VERSION 5.7 ;
  NOWIREEXTENSIONATPIN ON ;
  DIVIDERCHAR "/" ;
  BUSBITCHARS "[]" ;
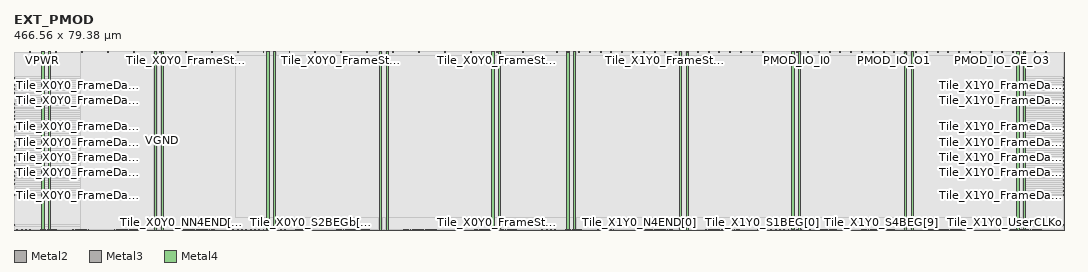
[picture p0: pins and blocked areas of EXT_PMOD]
MACRO EXT_PMOD
  CLASS BLOCK ;
  FOREIGN EXT_PMOD ;
  ORIGIN 0.000 0.000 ;
  SIZE 466.560 BY 79.380 ;
  PIN PMOD_IO_I0
    DIRECTION INPUT ;
    USE SIGNAL ;
    ANTENNAGATEAREA 0.226200 ;
    PORT
      LAYER Metal2 ;
        RECT 347.800 78.980 348.200 79.380 ;
    END
  END PMOD_IO_I0
  PIN PMOD_IO_I1
    DIRECTION INPUT ;
    USE SIGNAL ;
    ANTENNAGATEAREA 0.226200 ;
    PORT
      LAYER Metal2 ;
        RECT 352.600 78.980 353.000 79.380 ;
    END
  END PMOD_IO_I1
  PIN PMOD_IO_I2
    DIRECTION INPUT ;
    USE SIGNAL ;
    ANTENNAGATEAREA 0.226200 ;
    PORT
      LAYER Metal2 ;
        RECT 357.400 78.980 357.800 79.380 ;
    END
  END PMOD_IO_I2
  PIN PMOD_IO_I3
    DIRECTION INPUT ;
    USE SIGNAL ;
    ANTENNAGATEAREA 0.226200 ;
    PORT
      LAYER Metal2 ;
        RECT 362.200 78.980 362.600 79.380 ;
    END
  END PMOD_IO_I3
  PIN PMOD_IO_I4
    DIRECTION INPUT ;
    USE SIGNAL ;
    ANTENNAGATEAREA 0.226200 ;
    PORT
      LAYER Metal2 ;
        RECT 367.000 78.980 367.400 79.380 ;
    END
  END PMOD_IO_I4
  PIN PMOD_IO_I5
    DIRECTION INPUT ;
    USE SIGNAL ;
    ANTENNAGATEAREA 0.226200 ;
    PORT
      LAYER Metal2 ;
        RECT 371.800 78.980 372.200 79.380 ;
    END
  END PMOD_IO_I5
  PIN PMOD_IO_I6
    DIRECTION INPUT ;
    USE SIGNAL ;
    ANTENNAGATEAREA 0.226200 ;
    PORT
      LAYER Metal2 ;
        RECT 376.600 78.980 377.000 79.380 ;
    END
  END PMOD_IO_I6
  PIN PMOD_IO_I7
    DIRECTION INPUT ;
    USE SIGNAL ;
    ANTENNAGATEAREA 0.226200 ;
    PORT
      LAYER Metal2 ;
        RECT 381.400 78.980 381.800 79.380 ;
    END
  END PMOD_IO_I7
  PIN PMOD_IO_O0
    DIRECTION OUTPUT ;
    USE SIGNAL ;
    ANTENNADIFFAREA 2.677400 ;
    PORT
      LAYER Metal2 ;
        RECT 386.200 78.980 386.600 79.380 ;
    END
  END PMOD_IO_O0
  PIN PMOD_IO_O1
    DIRECTION OUTPUT ;
    USE SIGNAL ;
    ANTENNADIFFAREA 2.677400 ;
    PORT
      LAYER Metal2 ;
        RECT 391.000 78.980 391.400 79.380 ;
    END
  END PMOD_IO_O1
  PIN PMOD_IO_O2
    DIRECTION OUTPUT ;
    USE SIGNAL ;
    ANTENNADIFFAREA 2.677400 ;
    PORT
      LAYER Metal2 ;
        RECT 395.800 78.980 396.200 79.380 ;
    END
  END PMOD_IO_O2
  PIN PMOD_IO_O3
    DIRECTION OUTPUT ;
    USE SIGNAL ;
    ANTENNADIFFAREA 2.677400 ;
    PORT
      LAYER Metal2 ;
        RECT 400.600 78.980 401.000 79.380 ;
    END
  END PMOD_IO_O3
  PIN PMOD_IO_O4
    DIRECTION OUTPUT ;
    USE SIGNAL ;
    ANTENNADIFFAREA 2.677400 ;
    PORT
      LAYER Metal2 ;
        RECT 405.400 78.980 405.800 79.380 ;
    END
  END PMOD_IO_O4
  PIN PMOD_IO_O5
    DIRECTION OUTPUT ;
    USE SIGNAL ;
    ANTENNADIFFAREA 2.677400 ;
    PORT
      LAYER Metal2 ;
        RECT 410.200 78.980 410.600 79.380 ;
    END
  END PMOD_IO_O5
  PIN PMOD_IO_O6
    DIRECTION OUTPUT ;
    USE SIGNAL ;
    ANTENNADIFFAREA 2.677400 ;
    PORT
      LAYER Metal2 ;
        RECT 415.000 78.980 415.400 79.380 ;
    END
  END PMOD_IO_O6
  PIN PMOD_IO_O7
    DIRECTION OUTPUT ;
    USE SIGNAL ;
    ANTENNADIFFAREA 2.677400 ;
    PORT
      LAYER Metal2 ;
        RECT 419.800 78.980 420.200 79.380 ;
    END
  END PMOD_IO_O7
  PIN PMOD_IO_OE_O0
    DIRECTION OUTPUT ;
    USE SIGNAL ;
    ANTENNADIFFAREA 2.677400 ;
    PORT
      LAYER Metal2 ;
        RECT 424.600 78.980 425.000 79.380 ;
    END
  END PMOD_IO_OE_O0
  PIN PMOD_IO_OE_O1
    DIRECTION OUTPUT ;
    USE SIGNAL ;
    ANTENNADIFFAREA 3.151000 ;
    PORT
      LAYER Metal2 ;
        RECT 429.400 78.980 429.800 79.380 ;
    END
  END PMOD_IO_OE_O1
  PIN PMOD_IO_OE_O2
    DIRECTION OUTPUT ;
    USE SIGNAL ;
    ANTENNADIFFAREA 3.151000 ;
    PORT
      LAYER Metal2 ;
        RECT 434.200 78.980 434.600 79.380 ;
    END
  END PMOD_IO_OE_O2
  PIN PMOD_IO_OE_O3
    DIRECTION OUTPUT ;
    USE SIGNAL ;
    ANTENNADIFFAREA 3.151000 ;
    PORT
      LAYER Metal2 ;
        RECT 439.000 78.980 439.400 79.380 ;
    END
  END PMOD_IO_OE_O3
  PIN PMOD_IO_OE_O4
    DIRECTION OUTPUT ;
    USE SIGNAL ;
    ANTENNADIFFAREA 2.677400 ;
    PORT
      LAYER Metal2 ;
        RECT 443.800 78.980 444.200 79.380 ;
    END
  END PMOD_IO_OE_O4
  PIN PMOD_IO_OE_O5
    DIRECTION OUTPUT ;
    USE SIGNAL ;
    ANTENNADIFFAREA 2.677400 ;
    PORT
      LAYER Metal2 ;
        RECT 448.600 78.980 449.000 79.380 ;
    END
  END PMOD_IO_OE_O5
  PIN PMOD_IO_OE_O6
    DIRECTION OUTPUT ;
    USE SIGNAL ;
    ANTENNADIFFAREA 2.677400 ;
    PORT
      LAYER Metal2 ;
        RECT 453.400 78.980 453.800 79.380 ;
    END
  END PMOD_IO_OE_O6
  PIN PMOD_IO_OE_O7
    DIRECTION OUTPUT ;
    USE SIGNAL ;
    ANTENNADIFFAREA 3.151000 ;
    PORT
      LAYER Metal2 ;
        RECT 458.200 78.980 458.600 79.380 ;
    END
  END PMOD_IO_OE_O7
  PIN Tile_X0Y0_Ci
    DIRECTION INPUT ;
    USE SIGNAL ;
    PORT
      LAYER Metal2 ;
        RECT 97.240 0.000 97.640 0.400 ;
    END
  END Tile_X0Y0_Ci
  PIN Tile_X0Y0_FrameData[0]
    DIRECTION INPUT ;
    USE SIGNAL ;
    ANTENNAGATEAREA 1.084200 ;
    ANTENNADIFFAREA 36.277199 ;
    PORT
      LAYER Metal3 ;
        RECT 0.000 15.340 0.400 15.740 ;
    END
  END Tile_X0Y0_FrameData[0]
  PIN Tile_X0Y0_FrameData[10]
    DIRECTION INPUT ;
    USE SIGNAL ;
    ANTENNAGATEAREA 1.264900 ;
    ANTENNADIFFAREA 28.215599 ;
    PORT
      LAYER Metal3 ;
        RECT 0.000 32.140 0.400 32.540 ;
    END
  END Tile_X0Y0_FrameData[10]
  PIN Tile_X0Y0_FrameData[11]
    DIRECTION INPUT ;
    USE SIGNAL ;
    ANTENNAGATEAREA 1.264900 ;
    ANTENNADIFFAREA 28.215599 ;
    PORT
      LAYER Metal3 ;
        RECT 0.000 33.820 0.400 34.220 ;
    END
  END Tile_X0Y0_FrameData[11]
  PIN Tile_X0Y0_FrameData[12]
    DIRECTION INPUT ;
    USE SIGNAL ;
    ANTENNAGATEAREA 1.264900 ;
    ANTENNADIFFAREA 14.107800 ;
    PORT
      LAYER Metal3 ;
        RECT 0.000 35.500 0.400 35.900 ;
    END
  END Tile_X0Y0_FrameData[12]
  PIN Tile_X0Y0_FrameData[13]
    DIRECTION INPUT ;
    USE SIGNAL ;
    ANTENNAGATEAREA 1.264900 ;
    ANTENNADIFFAREA 84.646797 ;
    PORT
      LAYER Metal3 ;
        RECT 0.000 37.180 0.400 37.580 ;
    END
  END Tile_X0Y0_FrameData[13]
  PIN Tile_X0Y0_FrameData[14]
    DIRECTION INPUT ;
    USE SIGNAL ;
    ANTENNAGATEAREA 1.264900 ;
    PORT
      LAYER Metal3 ;
        RECT 0.000 38.860 0.400 39.260 ;
    END
  END Tile_X0Y0_FrameData[14]
  PIN Tile_X0Y0_FrameData[15]
    DIRECTION INPUT ;
    USE SIGNAL ;
    ANTENNAGATEAREA 1.445600 ;
    PORT
      LAYER Metal3 ;
        RECT 0.000 40.540 0.400 40.940 ;
    END
  END Tile_X0Y0_FrameData[15]
  PIN Tile_X0Y0_FrameData[16]
    DIRECTION INPUT ;
    USE SIGNAL ;
    ANTENNAGATEAREA 1.445600 ;
    PORT
      LAYER Metal3 ;
        RECT 0.000 42.220 0.400 42.620 ;
    END
  END Tile_X0Y0_FrameData[16]
  PIN Tile_X0Y0_FrameData[17]
    DIRECTION INPUT ;
    USE SIGNAL ;
    ANTENNAGATEAREA 1.445600 ;
    PORT
      LAYER Metal3 ;
        RECT 0.000 43.900 0.400 44.300 ;
    END
  END Tile_X0Y0_FrameData[17]
  PIN Tile_X0Y0_FrameData[18]
    DIRECTION INPUT ;
    USE SIGNAL ;
    ANTENNAGATEAREA 1.445600 ;
    PORT
      LAYER Metal3 ;
        RECT 0.000 45.580 0.400 45.980 ;
    END
  END Tile_X0Y0_FrameData[18]
  PIN Tile_X0Y0_FrameData[19]
    DIRECTION INPUT ;
    USE SIGNAL ;
    ANTENNAGATEAREA 1.445600 ;
    PORT
      LAYER Metal3 ;
        RECT 0.000 47.260 0.400 47.660 ;
    END
  END Tile_X0Y0_FrameData[19]
  PIN Tile_X0Y0_FrameData[1]
    DIRECTION INPUT ;
    USE SIGNAL ;
    ANTENNAGATEAREA 1.084200 ;
    ANTENNADIFFAREA 72.554398 ;
    PORT
      LAYER Metal3 ;
        RECT 0.000 17.020 0.400 17.420 ;
    END
  END Tile_X0Y0_FrameData[1]
  PIN Tile_X0Y0_FrameData[20]
    DIRECTION INPUT ;
    USE SIGNAL ;
    ANTENNAGATEAREA 1.445600 ;
    ANTENNADIFFAREA 16.123199 ;
    PORT
      LAYER Metal3 ;
        RECT 0.000 48.940 0.400 49.340 ;
    END
  END Tile_X0Y0_FrameData[20]
  PIN Tile_X0Y0_FrameData[21]
    DIRECTION INPUT ;
    USE SIGNAL ;
    ANTENNAGATEAREA 1.445600 ;
    PORT
      LAYER Metal3 ;
        RECT 0.000 50.620 0.400 51.020 ;
    END
  END Tile_X0Y0_FrameData[21]
  PIN Tile_X0Y0_FrameData[22]
    DIRECTION INPUT ;
    USE SIGNAL ;
    ANTENNAGATEAREA 1.445600 ;
    PORT
      LAYER Metal3 ;
        RECT 0.000 52.300 0.400 52.700 ;
    END
  END Tile_X0Y0_FrameData[22]
  PIN Tile_X0Y0_FrameData[23]
    DIRECTION INPUT ;
    USE SIGNAL ;
    ANTENNAGATEAREA 1.445600 ;
    PORT
      LAYER Metal3 ;
        RECT 0.000 53.980 0.400 54.380 ;
    END
  END Tile_X0Y0_FrameData[23]
  PIN Tile_X0Y0_FrameData[24]
    DIRECTION INPUT ;
    USE SIGNAL ;
    ANTENNAGATEAREA 1.445600 ;
    PORT
      LAYER Metal3 ;
        RECT 0.000 55.660 0.400 56.060 ;
    END
  END Tile_X0Y0_FrameData[24]
  PIN Tile_X0Y0_FrameData[25]
    DIRECTION INPUT ;
    USE SIGNAL ;
    ANTENNAGATEAREA 1.445600 ;
    PORT
      LAYER Metal3 ;
        RECT 0.000 57.340 0.400 57.740 ;
    END
  END Tile_X0Y0_FrameData[25]
  PIN Tile_X0Y0_FrameData[26]
    DIRECTION INPUT ;
    USE SIGNAL ;
    ANTENNAGATEAREA 1.445600 ;
    ANTENNADIFFAREA 128.985596 ;
    PORT
      LAYER Metal3 ;
        RECT 0.000 59.020 0.400 59.420 ;
    END
  END Tile_X0Y0_FrameData[26]
  PIN Tile_X0Y0_FrameData[27]
    DIRECTION INPUT ;
    USE SIGNAL ;
    ANTENNAGATEAREA 1.445600 ;
    ANTENNADIFFAREA 80.615997 ;
    PORT
      LAYER Metal3 ;
        RECT 0.000 60.700 0.400 61.100 ;
    END
  END Tile_X0Y0_FrameData[27]
  PIN Tile_X0Y0_FrameData[28]
    DIRECTION INPUT ;
    USE SIGNAL ;
    ANTENNAGATEAREA 1.445600 ;
    ANTENNADIFFAREA 16.123199 ;
    PORT
      LAYER Metal3 ;
        RECT 0.000 62.380 0.400 62.780 ;
    END
  END Tile_X0Y0_FrameData[28]
  PIN Tile_X0Y0_FrameData[29]
    DIRECTION INPUT ;
    USE SIGNAL ;
    ANTENNAGATEAREA 1.445600 ;
    PORT
      LAYER Metal3 ;
        RECT 0.000 64.060 0.400 64.460 ;
    END
  END Tile_X0Y0_FrameData[29]
  PIN Tile_X0Y0_FrameData[2]
    DIRECTION INPUT ;
    USE SIGNAL ;
    ANTENNAGATEAREA 1.084200 ;
    ANTENNADIFFAREA 72.554398 ;
    PORT
      LAYER Metal3 ;
        RECT 0.000 18.700 0.400 19.100 ;
    END
  END Tile_X0Y0_FrameData[2]
  PIN Tile_X0Y0_FrameData[30]
    DIRECTION INPUT ;
    USE SIGNAL ;
    ANTENNAGATEAREA 1.445600 ;
    PORT
      LAYER Metal3 ;
        RECT 0.000 65.740 0.400 66.140 ;
    END
  END Tile_X0Y0_FrameData[30]
  PIN Tile_X0Y0_FrameData[31]
    DIRECTION INPUT ;
    USE SIGNAL ;
    ANTENNAGATEAREA 1.445600 ;
    PORT
      LAYER Metal3 ;
        RECT 0.000 67.420 0.400 67.820 ;
    END
  END Tile_X0Y0_FrameData[31]
  PIN Tile_X0Y0_FrameData[3]
    DIRECTION INPUT ;
    USE SIGNAL ;
    ANTENNAGATEAREA 1.084200 ;
    ANTENNADIFFAREA 72.554398 ;
    PORT
      LAYER Metal3 ;
        RECT 0.000 20.380 0.400 20.780 ;
    END
  END Tile_X0Y0_FrameData[3]
  PIN Tile_X0Y0_FrameData[4]
    DIRECTION INPUT ;
    USE SIGNAL ;
    ANTENNAGATEAREA 1.264900 ;
    PORT
      LAYER Metal3 ;
        RECT 0.000 22.060 0.400 22.460 ;
    END
  END Tile_X0Y0_FrameData[4]
  PIN Tile_X0Y0_FrameData[5]
    DIRECTION INPUT ;
    USE SIGNAL ;
    ANTENNAGATEAREA 1.264900 ;
    ANTENNADIFFAREA 98.754601 ;
    PORT
      LAYER Metal3 ;
        RECT 0.000 23.740 0.400 24.140 ;
    END
  END Tile_X0Y0_FrameData[5]
  PIN Tile_X0Y0_FrameData[6]
    DIRECTION INPUT ;
    USE SIGNAL ;
    ANTENNAGATEAREA 1.264900 ;
    PORT
      LAYER Metal3 ;
        RECT 0.000 25.420 0.400 25.820 ;
    END
  END Tile_X0Y0_FrameData[6]
  PIN Tile_X0Y0_FrameData[7]
    DIRECTION INPUT ;
    USE SIGNAL ;
    ANTENNAGATEAREA 1.264900 ;
    ANTENNADIFFAREA 84.646797 ;
    PORT
      LAYER Metal3 ;
        RECT 0.000 27.100 0.400 27.500 ;
    END
  END Tile_X0Y0_FrameData[7]
  PIN Tile_X0Y0_FrameData[8]
    DIRECTION INPUT ;
    USE SIGNAL ;
    ANTENNAGATEAREA 1.264900 ;
    PORT
      LAYER Metal3 ;
        RECT 0.000 28.780 0.400 29.180 ;
    END
  END Tile_X0Y0_FrameData[8]
  PIN Tile_X0Y0_FrameData[9]
    DIRECTION INPUT ;
    USE SIGNAL ;
    ANTENNAGATEAREA 1.264900 ;
    ANTENNADIFFAREA 56.431198 ;
    PORT
      LAYER Metal3 ;
        RECT 0.000 30.460 0.400 30.860 ;
    END
  END Tile_X0Y0_FrameData[9]
  PIN Tile_X0Y0_FrameStrobe[0]
    DIRECTION INPUT ;
    USE SIGNAL ;
    ANTENNAGATEAREA 11.745500 ;
    PORT
      LAYER Metal2 ;
        RECT 204.760 0.000 205.160 0.400 ;
    END
  END Tile_X0Y0_FrameStrobe[0]
  PIN Tile_X0Y0_FrameStrobe[10]
    DIRECTION INPUT ;
    USE SIGNAL ;
    ANTENNAGATEAREA 0.180700 ;
    PORT
      LAYER Metal2 ;
        RECT 214.360 0.000 214.760 0.400 ;
    END
  END Tile_X0Y0_FrameStrobe[10]
  PIN Tile_X0Y0_FrameStrobe[11]
    DIRECTION INPUT ;
    USE SIGNAL ;
    ANTENNAGATEAREA 0.180700 ;
    PORT
      LAYER Metal2 ;
        RECT 215.320 0.000 215.720 0.400 ;
    END
  END Tile_X0Y0_FrameStrobe[11]
  PIN Tile_X0Y0_FrameStrobe[12]
    DIRECTION INPUT ;
    USE SIGNAL ;
    ANTENNAGATEAREA 0.180700 ;
    PORT
      LAYER Metal2 ;
        RECT 216.280 0.000 216.680 0.400 ;
    END
  END Tile_X0Y0_FrameStrobe[12]
  PIN Tile_X0Y0_FrameStrobe[13]
    DIRECTION INPUT ;
    USE SIGNAL ;
    ANTENNAGATEAREA 0.180700 ;
    PORT
      LAYER Metal2 ;
        RECT 217.240 0.000 217.640 0.400 ;
    END
  END Tile_X0Y0_FrameStrobe[13]
  PIN Tile_X0Y0_FrameStrobe[14]
    DIRECTION INPUT ;
    USE SIGNAL ;
    ANTENNAGATEAREA 0.180700 ;
    PORT
      LAYER Metal2 ;
        RECT 218.200 0.000 218.600 0.400 ;
    END
  END Tile_X0Y0_FrameStrobe[14]
  PIN Tile_X0Y0_FrameStrobe[15]
    DIRECTION INPUT ;
    USE SIGNAL ;
    ANTENNAGATEAREA 0.180700 ;
    PORT
      LAYER Metal2 ;
        RECT 219.160 0.000 219.560 0.400 ;
    END
  END Tile_X0Y0_FrameStrobe[15]
  PIN Tile_X0Y0_FrameStrobe[16]
    DIRECTION INPUT ;
    USE SIGNAL ;
    ANTENNAGATEAREA 0.180700 ;
    PORT
      LAYER Metal2 ;
        RECT 220.120 0.000 220.520 0.400 ;
    END
  END Tile_X0Y0_FrameStrobe[16]
  PIN Tile_X0Y0_FrameStrobe[17]
    DIRECTION INPUT ;
    USE SIGNAL ;
    ANTENNAGATEAREA 0.180700 ;
    PORT
      LAYER Metal2 ;
        RECT 221.080 0.000 221.480 0.400 ;
    END
  END Tile_X0Y0_FrameStrobe[17]
  PIN Tile_X0Y0_FrameStrobe[18]
    DIRECTION INPUT ;
    USE SIGNAL ;
    ANTENNAGATEAREA 0.180700 ;
    PORT
      LAYER Metal2 ;
        RECT 222.040 0.000 222.440 0.400 ;
    END
  END Tile_X0Y0_FrameStrobe[18]
  PIN Tile_X0Y0_FrameStrobe[19]
    DIRECTION INPUT ;
    USE SIGNAL ;
    ANTENNAGATEAREA 0.180700 ;
    PORT
      LAYER Metal2 ;
        RECT 223.000 0.000 223.400 0.400 ;
    END
  END Tile_X0Y0_FrameStrobe[19]
  PIN Tile_X0Y0_FrameStrobe[1]
    DIRECTION INPUT ;
    USE SIGNAL ;
    ANTENNAGATEAREA 11.745500 ;
    PORT
      LAYER Metal2 ;
        RECT 205.720 0.000 206.120 0.400 ;
    END
  END Tile_X0Y0_FrameStrobe[1]
  PIN Tile_X0Y0_FrameStrobe[2]
    DIRECTION INPUT ;
    USE SIGNAL ;
    ANTENNAGATEAREA 10.299900 ;
    PORT
      LAYER Metal2 ;
        RECT 206.680 0.000 207.080 0.400 ;
    END
  END Tile_X0Y0_FrameStrobe[2]
  PIN Tile_X0Y0_FrameStrobe[3]
    DIRECTION INPUT ;
    USE SIGNAL ;
    ANTENNAGATEAREA 0.180700 ;
    PORT
      LAYER Metal2 ;
        RECT 207.640 0.000 208.040 0.400 ;
    END
  END Tile_X0Y0_FrameStrobe[3]
  PIN Tile_X0Y0_FrameStrobe[4]
    DIRECTION INPUT ;
    USE SIGNAL ;
    ANTENNAGATEAREA 0.180700 ;
    PORT
      LAYER Metal2 ;
        RECT 208.600 0.000 209.000 0.400 ;
    END
  END Tile_X0Y0_FrameStrobe[4]
  PIN Tile_X0Y0_FrameStrobe[5]
    DIRECTION INPUT ;
    USE SIGNAL ;
    ANTENNAGATEAREA 0.180700 ;
    PORT
      LAYER Metal2 ;
        RECT 209.560 0.000 209.960 0.400 ;
    END
  END Tile_X0Y0_FrameStrobe[5]
  PIN Tile_X0Y0_FrameStrobe[6]
    DIRECTION INPUT ;
    USE SIGNAL ;
    ANTENNAGATEAREA 0.180700 ;
    PORT
      LAYER Metal2 ;
        RECT 210.520 0.000 210.920 0.400 ;
    END
  END Tile_X0Y0_FrameStrobe[6]
  PIN Tile_X0Y0_FrameStrobe[7]
    DIRECTION INPUT ;
    USE SIGNAL ;
    ANTENNAGATEAREA 0.180700 ;
    PORT
      LAYER Metal2 ;
        RECT 211.480 0.000 211.880 0.400 ;
    END
  END Tile_X0Y0_FrameStrobe[7]
  PIN Tile_X0Y0_FrameStrobe[8]
    DIRECTION INPUT ;
    USE SIGNAL ;
    ANTENNAGATEAREA 0.180700 ;
    PORT
      LAYER Metal2 ;
        RECT 212.440 0.000 212.840 0.400 ;
    END
  END Tile_X0Y0_FrameStrobe[8]
  PIN Tile_X0Y0_FrameStrobe[9]
    DIRECTION INPUT ;
    USE SIGNAL ;
    ANTENNAGATEAREA 0.180700 ;
    PORT
      LAYER Metal2 ;
        RECT 213.400 0.000 213.800 0.400 ;
    END
  END Tile_X0Y0_FrameStrobe[9]
  PIN Tile_X0Y0_FrameStrobe_O[0]
    DIRECTION OUTPUT ;
    USE SIGNAL ;
    ANTENNADIFFAREA 2.724000 ;
    PORT
      LAYER Metal2 ;
        RECT 7.000 78.980 7.400 79.380 ;
    END
  END Tile_X0Y0_FrameStrobe_O[0]
  PIN Tile_X0Y0_FrameStrobe_O[10]
    DIRECTION OUTPUT ;
    USE SIGNAL ;
    ANTENNADIFFAREA 2.724000 ;
    PORT
      LAYER Metal2 ;
        RECT 122.200 78.980 122.600 79.380 ;
    END
  END Tile_X0Y0_FrameStrobe_O[10]
  PIN Tile_X0Y0_FrameStrobe_O[11]
    DIRECTION OUTPUT ;
    USE SIGNAL ;
    ANTENNADIFFAREA 2.724000 ;
    PORT
      LAYER Metal2 ;
        RECT 133.720 78.980 134.120 79.380 ;
    END
  END Tile_X0Y0_FrameStrobe_O[11]
  PIN Tile_X0Y0_FrameStrobe_O[12]
    DIRECTION OUTPUT ;
    USE SIGNAL ;
    ANTENNADIFFAREA 2.724000 ;
    PORT
      LAYER Metal2 ;
        RECT 145.240 78.980 145.640 79.380 ;
    END
  END Tile_X0Y0_FrameStrobe_O[12]
  PIN Tile_X0Y0_FrameStrobe_O[13]
    DIRECTION OUTPUT ;
    USE SIGNAL ;
    ANTENNADIFFAREA 2.724000 ;
    PORT
      LAYER Metal2 ;
        RECT 156.760 78.980 157.160 79.380 ;
    END
  END Tile_X0Y0_FrameStrobe_O[13]
  PIN Tile_X0Y0_FrameStrobe_O[14]
    DIRECTION OUTPUT ;
    USE SIGNAL ;
    ANTENNADIFFAREA 2.724000 ;
    PORT
      LAYER Metal2 ;
        RECT 168.280 78.980 168.680 79.380 ;
    END
  END Tile_X0Y0_FrameStrobe_O[14]
  PIN Tile_X0Y0_FrameStrobe_O[15]
    DIRECTION OUTPUT ;
    USE SIGNAL ;
    ANTENNADIFFAREA 2.724000 ;
    PORT
      LAYER Metal2 ;
        RECT 179.800 78.980 180.200 79.380 ;
    END
  END Tile_X0Y0_FrameStrobe_O[15]
  PIN Tile_X0Y0_FrameStrobe_O[16]
    DIRECTION OUTPUT ;
    USE SIGNAL ;
    ANTENNADIFFAREA 2.724000 ;
    PORT
      LAYER Metal2 ;
        RECT 191.320 78.980 191.720 79.380 ;
    END
  END Tile_X0Y0_FrameStrobe_O[16]
  PIN Tile_X0Y0_FrameStrobe_O[17]
    DIRECTION OUTPUT ;
    USE SIGNAL ;
    ANTENNADIFFAREA 2.724000 ;
    PORT
      LAYER Metal2 ;
        RECT 202.840 78.980 203.240 79.380 ;
    END
  END Tile_X0Y0_FrameStrobe_O[17]
  PIN Tile_X0Y0_FrameStrobe_O[18]
    DIRECTION OUTPUT ;
    USE SIGNAL ;
    ANTENNADIFFAREA 2.724000 ;
    PORT
      LAYER Metal2 ;
        RECT 214.360 78.980 214.760 79.380 ;
    END
  END Tile_X0Y0_FrameStrobe_O[18]
  PIN Tile_X0Y0_FrameStrobe_O[19]
    DIRECTION OUTPUT ;
    USE SIGNAL ;
    ANTENNADIFFAREA 2.724000 ;
    PORT
      LAYER Metal2 ;
        RECT 225.880 78.980 226.280 79.380 ;
    END
  END Tile_X0Y0_FrameStrobe_O[19]
  PIN Tile_X0Y0_FrameStrobe_O[1]
    DIRECTION OUTPUT ;
    USE SIGNAL ;
    ANTENNADIFFAREA 2.724000 ;
    PORT
      LAYER Metal2 ;
        RECT 18.520 78.980 18.920 79.380 ;
    END
  END Tile_X0Y0_FrameStrobe_O[1]
  PIN Tile_X0Y0_FrameStrobe_O[2]
    DIRECTION OUTPUT ;
    USE SIGNAL ;
    ANTENNADIFFAREA 2.724000 ;
    PORT
      LAYER Metal2 ;
        RECT 30.040 78.980 30.440 79.380 ;
    END
  END Tile_X0Y0_FrameStrobe_O[2]
  PIN Tile_X0Y0_FrameStrobe_O[3]
    DIRECTION OUTPUT ;
    USE SIGNAL ;
    ANTENNADIFFAREA 2.724000 ;
    PORT
      LAYER Metal2 ;
        RECT 41.560 78.980 41.960 79.380 ;
    END
  END Tile_X0Y0_FrameStrobe_O[3]
  PIN Tile_X0Y0_FrameStrobe_O[4]
    DIRECTION OUTPUT ;
    USE SIGNAL ;
    ANTENNADIFFAREA 2.724000 ;
    PORT
      LAYER Metal2 ;
        RECT 53.080 78.980 53.480 79.380 ;
    END
  END Tile_X0Y0_FrameStrobe_O[4]
  PIN Tile_X0Y0_FrameStrobe_O[5]
    DIRECTION OUTPUT ;
    USE SIGNAL ;
    ANTENNADIFFAREA 2.724000 ;
    PORT
      LAYER Metal2 ;
        RECT 64.600 78.980 65.000 79.380 ;
    END
  END Tile_X0Y0_FrameStrobe_O[5]
  PIN Tile_X0Y0_FrameStrobe_O[6]
    DIRECTION OUTPUT ;
    USE SIGNAL ;
    ANTENNADIFFAREA 2.724000 ;
    PORT
      LAYER Metal2 ;
        RECT 76.120 78.980 76.520 79.380 ;
    END
  END Tile_X0Y0_FrameStrobe_O[6]
  PIN Tile_X0Y0_FrameStrobe_O[7]
    DIRECTION OUTPUT ;
    USE SIGNAL ;
    ANTENNADIFFAREA 2.724000 ;
    PORT
      LAYER Metal2 ;
        RECT 87.640 78.980 88.040 79.380 ;
    END
  END Tile_X0Y0_FrameStrobe_O[7]
  PIN Tile_X0Y0_FrameStrobe_O[8]
    DIRECTION OUTPUT ;
    USE SIGNAL ;
    ANTENNADIFFAREA 2.724000 ;
    PORT
      LAYER Metal2 ;
        RECT 99.160 78.980 99.560 79.380 ;
    END
  END Tile_X0Y0_FrameStrobe_O[8]
  PIN Tile_X0Y0_FrameStrobe_O[9]
    DIRECTION OUTPUT ;
    USE SIGNAL ;
    ANTENNADIFFAREA 2.724000 ;
    PORT
      LAYER Metal2 ;
        RECT 110.680 78.980 111.080 79.380 ;
    END
  END Tile_X0Y0_FrameStrobe_O[9]
  PIN Tile_X0Y0_N1END[0]
    DIRECTION INPUT ;
    USE SIGNAL ;
    ANTENNAGATEAREA 0.607100 ;
    PORT
      LAYER Metal2 ;
        RECT 1.240 0.000 1.640 0.400 ;
    END
  END Tile_X0Y0_N1END[0]
  PIN Tile_X0Y0_N1END[1]
    DIRECTION INPUT ;
    USE SIGNAL ;
    ANTENNAGATEAREA 0.607100 ;
    PORT
      LAYER Metal2 ;
        RECT 3.160 0.000 3.560 0.400 ;
    END
  END Tile_X0Y0_N1END[1]
  PIN Tile_X0Y0_N1END[2]
    DIRECTION INPUT ;
    USE SIGNAL ;
    ANTENNAGATEAREA 0.607100 ;
    PORT
      LAYER Metal2 ;
        RECT 5.080 0.000 5.480 0.400 ;
    END
  END Tile_X0Y0_N1END[2]
  PIN Tile_X0Y0_N1END[3]
    DIRECTION INPUT ;
    USE SIGNAL ;
    ANTENNAGATEAREA 0.607100 ;
    PORT
      LAYER Metal2 ;
        RECT 7.000 0.000 7.400 0.400 ;
    END
  END Tile_X0Y0_N1END[3]
  PIN Tile_X0Y0_N2END[0]
    DIRECTION INPUT ;
    USE SIGNAL ;
    ANTENNAGATEAREA 0.639600 ;
    PORT
      LAYER Metal2 ;
        RECT 26.200 0.000 26.600 0.400 ;
    END
  END Tile_X0Y0_N2END[0]
  PIN Tile_X0Y0_N2END[1]
    DIRECTION INPUT ;
    USE SIGNAL ;
    ANTENNAGATEAREA 0.639600 ;
    PORT
      LAYER Metal2 ;
        RECT 27.160 0.000 27.560 0.400 ;
    END
  END Tile_X0Y0_N2END[1]
  PIN Tile_X0Y0_N2END[2]
    DIRECTION INPUT ;
    USE SIGNAL ;
    ANTENNAGATEAREA 0.852800 ;
    PORT
      LAYER Metal2 ;
        RECT 28.120 0.000 28.520 0.400 ;
    END
  END Tile_X0Y0_N2END[2]
  PIN Tile_X0Y0_N2END[3]
    DIRECTION INPUT ;
    USE SIGNAL ;
    ANTENNAGATEAREA 0.852800 ;
    PORT
      LAYER Metal2 ;
        RECT 29.080 0.000 29.480 0.400 ;
    END
  END Tile_X0Y0_N2END[3]
  PIN Tile_X0Y0_N2END[4]
    DIRECTION INPUT ;
    USE SIGNAL ;
    ANTENNAGATEAREA 0.852800 ;
    ANTENNADIFFAREA 32.246399 ;
    PORT
      LAYER Metal2 ;
        RECT 30.040 0.000 30.440 0.400 ;
    END
  END Tile_X0Y0_N2END[4]
  PIN Tile_X0Y0_N2END[5]
    DIRECTION INPUT ;
    USE SIGNAL ;
    ANTENNAGATEAREA 0.852800 ;
    PORT
      LAYER Metal2 ;
        RECT 31.000 0.000 31.400 0.400 ;
    END
  END Tile_X0Y0_N2END[5]
  PIN Tile_X0Y0_N2END[6]
    DIRECTION INPUT ;
    USE SIGNAL ;
    ANTENNAGATEAREA 0.852800 ;
    PORT
      LAYER Metal2 ;
        RECT 31.960 0.000 32.360 0.400 ;
    END
  END Tile_X0Y0_N2END[6]
  PIN Tile_X0Y0_N2END[7]
    DIRECTION INPUT ;
    USE SIGNAL ;
    ANTENNAGATEAREA 0.852800 ;
    PORT
      LAYER Metal2 ;
        RECT 32.920 0.000 33.320 0.400 ;
    END
  END Tile_X0Y0_N2END[7]
  PIN Tile_X0Y0_N2MID[0]
    DIRECTION INPUT ;
    USE SIGNAL ;
    ANTENNAGATEAREA 1.033500 ;
    PORT
      LAYER Metal2 ;
        RECT 11.800 0.000 12.200 0.400 ;
    END
  END Tile_X0Y0_N2MID[0]
  PIN Tile_X0Y0_N2MID[1]
    DIRECTION INPUT ;
    USE SIGNAL ;
    ANTENNAGATEAREA 1.033500 ;
    PORT
      LAYER Metal2 ;
        RECT 12.760 0.000 13.160 0.400 ;
    END
  END Tile_X0Y0_N2MID[1]
  PIN Tile_X0Y0_N2MID[2]
    DIRECTION INPUT ;
    USE SIGNAL ;
    ANTENNAGATEAREA 1.033500 ;
    PORT
      LAYER Metal2 ;
        RECT 13.720 0.000 14.120 0.400 ;
    END
  END Tile_X0Y0_N2MID[2]
  PIN Tile_X0Y0_N2MID[3]
    DIRECTION INPUT ;
    USE SIGNAL ;
    ANTENNAGATEAREA 1.033500 ;
    PORT
      LAYER Metal2 ;
        RECT 14.680 0.000 15.080 0.400 ;
    END
  END Tile_X0Y0_N2MID[3]
  PIN Tile_X0Y0_N2MID[4]
    DIRECTION INPUT ;
    USE SIGNAL ;
    ANTENNAGATEAREA 1.033500 ;
    PORT
      LAYER Metal2 ;
        RECT 15.640 0.000 16.040 0.400 ;
    END
  END Tile_X0Y0_N2MID[4]
  PIN Tile_X0Y0_N2MID[5]
    DIRECTION INPUT ;
    USE SIGNAL ;
    ANTENNAGATEAREA 1.033500 ;
    PORT
      LAYER Metal2 ;
        RECT 16.600 0.000 17.000 0.400 ;
    END
  END Tile_X0Y0_N2MID[5]
  PIN Tile_X0Y0_N2MID[6]
    DIRECTION INPUT ;
    USE SIGNAL ;
    ANTENNAGATEAREA 0.820300 ;
    PORT
      LAYER Metal2 ;
        RECT 17.560 0.000 17.960 0.400 ;
    END
  END Tile_X0Y0_N2MID[6]
  PIN Tile_X0Y0_N2MID[7]
    DIRECTION INPUT ;
    USE SIGNAL ;
    ANTENNAGATEAREA 0.820300 ;
    PORT
      LAYER Metal2 ;
        RECT 18.520 0.000 18.920 0.400 ;
    END
  END Tile_X0Y0_N2MID[7]
  PIN Tile_X0Y0_N4END[0]
    DIRECTION INPUT ;
    USE SIGNAL ;
    ANTENNAGATEAREA 0.426400 ;
    PORT
      LAYER Metal2 ;
        RECT 44.440 0.000 44.840 0.400 ;
    END
  END Tile_X0Y0_N4END[0]
  PIN Tile_X0Y0_N4END[10]
    DIRECTION INPUT ;
    USE SIGNAL ;
    ANTENNAGATEAREA 0.639600 ;
    PORT
      LAYER Metal2 ;
        RECT 54.040 0.000 54.440 0.400 ;
    END
  END Tile_X0Y0_N4END[10]
  PIN Tile_X0Y0_N4END[11]
    DIRECTION INPUT ;
    USE SIGNAL ;
    ANTENNAGATEAREA 0.639600 ;
    PORT
      LAYER Metal2 ;
        RECT 55.000 0.000 55.400 0.400 ;
    END
  END Tile_X0Y0_N4END[11]
  PIN Tile_X0Y0_N4END[12]
    DIRECTION INPUT ;
    USE SIGNAL ;
    ANTENNAGATEAREA 0.639600 ;
    PORT
      LAYER Metal2 ;
        RECT 55.960 0.000 56.360 0.400 ;
    END
  END Tile_X0Y0_N4END[12]
  PIN Tile_X0Y0_N4END[13]
    DIRECTION INPUT ;
    USE SIGNAL ;
    ANTENNAGATEAREA 0.639600 ;
    PORT
      LAYER Metal2 ;
        RECT 56.920 0.000 57.320 0.400 ;
    END
  END Tile_X0Y0_N4END[13]
  PIN Tile_X0Y0_N4END[14]
    DIRECTION INPUT ;
    USE SIGNAL ;
    ANTENNAGATEAREA 0.426400 ;
    ANTENNADIFFAREA 8.061600 ;
    PORT
      LAYER Metal2 ;
        RECT 57.880 0.000 58.280 0.400 ;
    END
  END Tile_X0Y0_N4END[14]
  PIN Tile_X0Y0_N4END[15]
    DIRECTION INPUT ;
    USE SIGNAL ;
    ANTENNAGATEAREA 0.426400 ;
    PORT
      LAYER Metal2 ;
        RECT 58.840 0.000 59.240 0.400 ;
    END
  END Tile_X0Y0_N4END[15]
  PIN Tile_X0Y0_N4END[1]
    DIRECTION INPUT ;
    USE SIGNAL ;
    ANTENNAGATEAREA 0.426400 ;
    PORT
      LAYER Metal2 ;
        RECT 45.400 0.000 45.800 0.400 ;
    END
  END Tile_X0Y0_N4END[1]
  PIN Tile_X0Y0_N4END[2]
    DIRECTION INPUT ;
    USE SIGNAL ;
    ANTENNAGATEAREA 0.426400 ;
    PORT
      LAYER Metal2 ;
        RECT 46.360 0.000 46.760 0.400 ;
    END
  END Tile_X0Y0_N4END[2]
  PIN Tile_X0Y0_N4END[3]
    DIRECTION INPUT ;
    USE SIGNAL ;
    ANTENNAGATEAREA 0.426400 ;
    ANTENNADIFFAREA 8.061600 ;
    PORT
      LAYER Metal2 ;
        RECT 47.320 0.000 47.720 0.400 ;
    END
  END Tile_X0Y0_N4END[3]
  PIN Tile_X0Y0_N4END[4]
    DIRECTION INPUT ;
    USE SIGNAL ;
    ANTENNAGATEAREA 0.426400 ;
    PORT
      LAYER Metal2 ;
        RECT 48.280 0.000 48.680 0.400 ;
    END
  END Tile_X0Y0_N4END[4]
  PIN Tile_X0Y0_N4END[5]
    DIRECTION INPUT ;
    USE SIGNAL ;
    ANTENNAGATEAREA 0.426400 ;
    PORT
      LAYER Metal2 ;
        RECT 49.240 0.000 49.640 0.400 ;
    END
  END Tile_X0Y0_N4END[5]
  PIN Tile_X0Y0_N4END[6]
    DIRECTION INPUT ;
    USE SIGNAL ;
    ANTENNAGATEAREA 0.426400 ;
    PORT
      LAYER Metal2 ;
        RECT 50.200 0.000 50.600 0.400 ;
    END
  END Tile_X0Y0_N4END[6]
  PIN Tile_X0Y0_N4END[7]
    DIRECTION INPUT ;
    USE SIGNAL ;
    ANTENNAGATEAREA 0.426400 ;
    PORT
      LAYER Metal2 ;
        RECT 51.160 0.000 51.560 0.400 ;
    END
  END Tile_X0Y0_N4END[7]
  PIN Tile_X0Y0_N4END[8]
    DIRECTION INPUT ;
    USE SIGNAL ;
    ANTENNAGATEAREA 0.639600 ;
    PORT
      LAYER Metal2 ;
        RECT 52.120 0.000 52.520 0.400 ;
    END
  END Tile_X0Y0_N4END[8]
  PIN Tile_X0Y0_N4END[9]
    DIRECTION INPUT ;
    USE SIGNAL ;
    ANTENNAGATEAREA 0.639600 ;
    PORT
      LAYER Metal2 ;
        RECT 53.080 0.000 53.480 0.400 ;
    END
  END Tile_X0Y0_N4END[9]
  PIN Tile_X0Y0_NN4END[0]
    DIRECTION INPUT ;
    USE SIGNAL ;
    ANTENNAGATEAREA 0.426400 ;
    PORT
      LAYER Metal2 ;
        RECT 74.200 0.000 74.600 0.400 ;
    END
  END Tile_X0Y0_NN4END[0]
  PIN Tile_X0Y0_NN4END[10]
    DIRECTION INPUT ;
    USE SIGNAL ;
    ANTENNAGATEAREA 0.639600 ;
    PORT
      LAYER Metal2 ;
        RECT 83.800 0.000 84.200 0.400 ;
    END
  END Tile_X0Y0_NN4END[10]
  PIN Tile_X0Y0_NN4END[11]
    DIRECTION INPUT ;
    USE SIGNAL ;
    ANTENNAGATEAREA 0.639600 ;
    PORT
      LAYER Metal2 ;
        RECT 84.760 0.000 85.160 0.400 ;
    END
  END Tile_X0Y0_NN4END[11]
  PIN Tile_X0Y0_NN4END[12]
    DIRECTION INPUT ;
    USE SIGNAL ;
    ANTENNAGATEAREA 0.639600 ;
    PORT
      LAYER Metal2 ;
        RECT 85.720 0.000 86.120 0.400 ;
    END
  END Tile_X0Y0_NN4END[12]
  PIN Tile_X0Y0_NN4END[13]
    DIRECTION INPUT ;
    USE SIGNAL ;
    ANTENNAGATEAREA 0.639600 ;
    PORT
      LAYER Metal2 ;
        RECT 86.680 0.000 87.080 0.400 ;
    END
  END Tile_X0Y0_NN4END[13]
  PIN Tile_X0Y0_NN4END[14]
    DIRECTION INPUT ;
    USE SIGNAL ;
    ANTENNAGATEAREA 0.426400 ;
    PORT
      LAYER Metal2 ;
        RECT 87.640 0.000 88.040 0.400 ;
    END
  END Tile_X0Y0_NN4END[14]
  PIN Tile_X0Y0_NN4END[15]
    DIRECTION INPUT ;
    USE SIGNAL ;
    ANTENNAGATEAREA 0.426400 ;
    PORT
      LAYER Metal2 ;
        RECT 88.600 0.000 89.000 0.400 ;
    END
  END Tile_X0Y0_NN4END[15]
  PIN Tile_X0Y0_NN4END[1]
    DIRECTION INPUT ;
    USE SIGNAL ;
    ANTENNAGATEAREA 0.426400 ;
    PORT
      LAYER Metal2 ;
        RECT 75.160 0.000 75.560 0.400 ;
    END
  END Tile_X0Y0_NN4END[1]
  PIN Tile_X0Y0_NN4END[2]
    DIRECTION INPUT ;
    USE SIGNAL ;
    ANTENNAGATEAREA 0.426400 ;
    PORT
      LAYER Metal2 ;
        RECT 76.120 0.000 76.520 0.400 ;
    END
  END Tile_X0Y0_NN4END[2]
  PIN Tile_X0Y0_NN4END[3]
    DIRECTION INPUT ;
    USE SIGNAL ;
    ANTENNAGATEAREA 0.426400 ;
    PORT
      LAYER Metal2 ;
        RECT 77.080 0.000 77.480 0.400 ;
    END
  END Tile_X0Y0_NN4END[3]
  PIN Tile_X0Y0_NN4END[4]
    DIRECTION INPUT ;
    USE SIGNAL ;
    ANTENNAGATEAREA 0.426400 ;
    PORT
      LAYER Metal2 ;
        RECT 78.040 0.000 78.440 0.400 ;
    END
  END Tile_X0Y0_NN4END[4]
  PIN Tile_X0Y0_NN4END[5]
    DIRECTION INPUT ;
    USE SIGNAL ;
    ANTENNAGATEAREA 0.426400 ;
    PORT
      LAYER Metal2 ;
        RECT 79.000 0.000 79.400 0.400 ;
    END
  END Tile_X0Y0_NN4END[5]
  PIN Tile_X0Y0_NN4END[6]
    DIRECTION INPUT ;
    USE SIGNAL ;
    ANTENNAGATEAREA 0.426400 ;
    PORT
      LAYER Metal2 ;
        RECT 79.960 0.000 80.360 0.400 ;
    END
  END Tile_X0Y0_NN4END[6]
  PIN Tile_X0Y0_NN4END[7]
    DIRECTION INPUT ;
    USE SIGNAL ;
    ANTENNAGATEAREA 0.426400 ;
    PORT
      LAYER Metal2 ;
        RECT 80.920 0.000 81.320 0.400 ;
    END
  END Tile_X0Y0_NN4END[7]
  PIN Tile_X0Y0_NN4END[8]
    DIRECTION INPUT ;
    USE SIGNAL ;
    ANTENNAGATEAREA 0.639600 ;
    PORT
      LAYER Metal2 ;
        RECT 81.880 0.000 82.280 0.400 ;
    END
  END Tile_X0Y0_NN4END[8]
  PIN Tile_X0Y0_NN4END[9]
    DIRECTION INPUT ;
    USE SIGNAL ;
    ANTENNAGATEAREA 0.639600 ;
    PORT
      LAYER Metal2 ;
        RECT 82.840 0.000 83.240 0.400 ;
    END
  END Tile_X0Y0_NN4END[9]
  PIN Tile_X0Y0_S1BEG[0]
    DIRECTION OUTPUT ;
    USE SIGNAL ;
    ANTENNADIFFAREA 2.724000 ;
    PORT
      LAYER Metal2 ;
        RECT 99.160 0.000 99.560 0.400 ;
    END
  END Tile_X0Y0_S1BEG[0]
  PIN Tile_X0Y0_S1BEG[1]
    DIRECTION OUTPUT ;
    USE SIGNAL ;
    ANTENNADIFFAREA 2.724000 ;
    PORT
      LAYER Metal2 ;
        RECT 101.080 0.000 101.480 0.400 ;
    END
  END Tile_X0Y0_S1BEG[1]
  PIN Tile_X0Y0_S1BEG[2]
    DIRECTION OUTPUT ;
    USE SIGNAL ;
    ANTENNADIFFAREA 2.724000 ;
    PORT
      LAYER Metal2 ;
        RECT 103.000 0.000 103.400 0.400 ;
    END
  END Tile_X0Y0_S1BEG[2]
  PIN Tile_X0Y0_S1BEG[3]
    DIRECTION OUTPUT ;
    USE SIGNAL ;
    ANTENNADIFFAREA 2.724000 ;
    PORT
      LAYER Metal2 ;
        RECT 104.920 0.000 105.320 0.400 ;
    END
  END Tile_X0Y0_S1BEG[3]
  PIN Tile_X0Y0_S2BEG[0]
    DIRECTION OUTPUT ;
    USE SIGNAL ;
    ANTENNADIFFAREA 2.724000 ;
    PORT
      LAYER Metal2 ;
        RECT 106.840 0.000 107.240 0.400 ;
    END
  END Tile_X0Y0_S2BEG[0]
  PIN Tile_X0Y0_S2BEG[1]
    DIRECTION OUTPUT ;
    USE SIGNAL ;
    ANTENNADIFFAREA 2.724000 ;
    PORT
      LAYER Metal2 ;
        RECT 108.760 0.000 109.160 0.400 ;
    END
  END Tile_X0Y0_S2BEG[1]
  PIN Tile_X0Y0_S2BEG[2]
    DIRECTION OUTPUT ;
    USE SIGNAL ;
    ANTENNADIFFAREA 2.724000 ;
    PORT
      LAYER Metal2 ;
        RECT 110.680 0.000 111.080 0.400 ;
    END
  END Tile_X0Y0_S2BEG[2]
  PIN Tile_X0Y0_S2BEG[3]
    DIRECTION OUTPUT ;
    USE SIGNAL ;
    ANTENNADIFFAREA 2.724000 ;
    PORT
      LAYER Metal2 ;
        RECT 112.600 0.000 113.000 0.400 ;
    END
  END Tile_X0Y0_S2BEG[3]
  PIN Tile_X0Y0_S2BEG[4]
    DIRECTION OUTPUT ;
    USE SIGNAL ;
    ANTENNADIFFAREA 2.724000 ;
    PORT
      LAYER Metal2 ;
        RECT 114.520 0.000 114.920 0.400 ;
    END
  END Tile_X0Y0_S2BEG[4]
  PIN Tile_X0Y0_S2BEG[5]
    DIRECTION OUTPUT ;
    USE SIGNAL ;
    ANTENNADIFFAREA 2.724000 ;
    PORT
      LAYER Metal2 ;
        RECT 116.440 0.000 116.840 0.400 ;
    END
  END Tile_X0Y0_S2BEG[5]
  PIN Tile_X0Y0_S2BEG[6]
    DIRECTION OUTPUT ;
    USE SIGNAL ;
    ANTENNADIFFAREA 2.724000 ;
    PORT
      LAYER Metal2 ;
        RECT 118.360 0.000 118.760 0.400 ;
    END
  END Tile_X0Y0_S2BEG[6]
  PIN Tile_X0Y0_S2BEG[7]
    DIRECTION OUTPUT ;
    USE SIGNAL ;
    ANTENNADIFFAREA 2.724000 ;
    PORT
      LAYER Metal2 ;
        RECT 120.280 0.000 120.680 0.400 ;
    END
  END Tile_X0Y0_S2BEG[7]
  PIN Tile_X0Y0_S2BEGb[0]
    DIRECTION OUTPUT ;
    USE SIGNAL ;
    ANTENNADIFFAREA 2.724000 ;
    PORT
      LAYER Metal2 ;
        RECT 125.080 0.000 125.480 0.400 ;
    END
  END Tile_X0Y0_S2BEGb[0]
  PIN Tile_X0Y0_S2BEGb[1]
    DIRECTION OUTPUT ;
    USE SIGNAL ;
    ANTENNADIFFAREA 2.724000 ;
    PORT
      LAYER Metal2 ;
        RECT 126.040 0.000 126.440 0.400 ;
    END
  END Tile_X0Y0_S2BEGb[1]
  PIN Tile_X0Y0_S2BEGb[2]
    DIRECTION OUTPUT ;
    USE SIGNAL ;
    ANTENNADIFFAREA 2.724000 ;
    PORT
      LAYER Metal2 ;
        RECT 127.000 0.000 127.400 0.400 ;
    END
  END Tile_X0Y0_S2BEGb[2]
  PIN Tile_X0Y0_S2BEGb[3]
    DIRECTION OUTPUT ;
    USE SIGNAL ;
    ANTENNADIFFAREA 2.724000 ;
    PORT
      LAYER Metal2 ;
        RECT 127.960 0.000 128.360 0.400 ;
    END
  END Tile_X0Y0_S2BEGb[3]
  PIN Tile_X0Y0_S2BEGb[4]
    DIRECTION OUTPUT ;
    USE SIGNAL ;
    ANTENNADIFFAREA 2.724000 ;
    PORT
      LAYER Metal2 ;
        RECT 128.920 0.000 129.320 0.400 ;
    END
  END Tile_X0Y0_S2BEGb[4]
  PIN Tile_X0Y0_S2BEGb[5]
    DIRECTION OUTPUT ;
    USE SIGNAL ;
    ANTENNADIFFAREA 2.724000 ;
    PORT
      LAYER Metal2 ;
        RECT 129.880 0.000 130.280 0.400 ;
    END
  END Tile_X0Y0_S2BEGb[5]
  PIN Tile_X0Y0_S2BEGb[6]
    DIRECTION OUTPUT ;
    USE SIGNAL ;
    ANTENNADIFFAREA 2.724000 ;
    PORT
      LAYER Metal2 ;
        RECT 130.840 0.000 131.240 0.400 ;
    END
  END Tile_X0Y0_S2BEGb[6]
  PIN Tile_X0Y0_S2BEGb[7]
    DIRECTION OUTPUT ;
    USE SIGNAL ;
    ANTENNADIFFAREA 2.724000 ;
    PORT
      LAYER Metal2 ;
        RECT 131.800 0.000 132.200 0.400 ;
    END
  END Tile_X0Y0_S2BEGb[7]
  PIN Tile_X0Y0_S4BEG[0]
    DIRECTION OUTPUT ;
    USE SIGNAL ;
    ANTENNADIFFAREA 2.724000 ;
    PORT
      LAYER Metal2 ;
        RECT 143.320 0.000 143.720 0.400 ;
    END
  END Tile_X0Y0_S4BEG[0]
  PIN Tile_X0Y0_S4BEG[10]
    DIRECTION OUTPUT ;
    USE SIGNAL ;
    ANTENNADIFFAREA 2.724000 ;
    PORT
      LAYER Metal2 ;
        RECT 152.920 0.000 153.320 0.400 ;
    END
  END Tile_X0Y0_S4BEG[10]
  PIN Tile_X0Y0_S4BEG[11]
    DIRECTION OUTPUT ;
    USE SIGNAL ;
    ANTENNADIFFAREA 2.724000 ;
    PORT
      LAYER Metal2 ;
        RECT 153.880 0.000 154.280 0.400 ;
    END
  END Tile_X0Y0_S4BEG[11]
  PIN Tile_X0Y0_S4BEG[12]
    DIRECTION OUTPUT ;
    USE SIGNAL ;
    ANTENNADIFFAREA 2.724000 ;
    PORT
      LAYER Metal2 ;
        RECT 154.840 0.000 155.240 0.400 ;
    END
  END Tile_X0Y0_S4BEG[12]
  PIN Tile_X0Y0_S4BEG[13]
    DIRECTION OUTPUT ;
    USE SIGNAL ;
    ANTENNADIFFAREA 2.724000 ;
    PORT
      LAYER Metal2 ;
        RECT 155.800 0.000 156.200 0.400 ;
    END
  END Tile_X0Y0_S4BEG[13]
  PIN Tile_X0Y0_S4BEG[14]
    DIRECTION OUTPUT ;
    USE SIGNAL ;
    ANTENNADIFFAREA 2.724000 ;
    PORT
      LAYER Metal2 ;
        RECT 156.760 0.000 157.160 0.400 ;
    END
  END Tile_X0Y0_S4BEG[14]
  PIN Tile_X0Y0_S4BEG[15]
    DIRECTION OUTPUT ;
    USE SIGNAL ;
    ANTENNADIFFAREA 2.724000 ;
    PORT
      LAYER Metal2 ;
        RECT 157.720 0.000 158.120 0.400 ;
    END
  END Tile_X0Y0_S4BEG[15]
  PIN Tile_X0Y0_S4BEG[1]
    DIRECTION OUTPUT ;
    USE SIGNAL ;
    ANTENNADIFFAREA 2.724000 ;
    PORT
      LAYER Metal2 ;
        RECT 144.280 0.000 144.680 0.400 ;
    END
  END Tile_X0Y0_S4BEG[1]
  PIN Tile_X0Y0_S4BEG[2]
    DIRECTION OUTPUT ;
    USE SIGNAL ;
    ANTENNADIFFAREA 2.724000 ;
    PORT
      LAYER Metal2 ;
        RECT 145.240 0.000 145.640 0.400 ;
    END
  END Tile_X0Y0_S4BEG[2]
  PIN Tile_X0Y0_S4BEG[3]
    DIRECTION OUTPUT ;
    USE SIGNAL ;
    ANTENNADIFFAREA 2.724000 ;
    PORT
      LAYER Metal2 ;
        RECT 146.200 0.000 146.600 0.400 ;
    END
  END Tile_X0Y0_S4BEG[3]
  PIN Tile_X0Y0_S4BEG[4]
    DIRECTION OUTPUT ;
    USE SIGNAL ;
    ANTENNADIFFAREA 2.724000 ;
    PORT
      LAYER Metal2 ;
        RECT 147.160 0.000 147.560 0.400 ;
    END
  END Tile_X0Y0_S4BEG[4]
  PIN Tile_X0Y0_S4BEG[5]
    DIRECTION OUTPUT ;
    USE SIGNAL ;
    ANTENNADIFFAREA 2.724000 ;
    PORT
      LAYER Metal2 ;
        RECT 148.120 0.000 148.520 0.400 ;
    END
  END Tile_X0Y0_S4BEG[5]
  PIN Tile_X0Y0_S4BEG[6]
    DIRECTION OUTPUT ;
    USE SIGNAL ;
    ANTENNADIFFAREA 2.724000 ;
    PORT
      LAYER Metal2 ;
        RECT 149.080 0.000 149.480 0.400 ;
    END
  END Tile_X0Y0_S4BEG[6]
  PIN Tile_X0Y0_S4BEG[7]
    DIRECTION OUTPUT ;
    USE SIGNAL ;
    ANTENNADIFFAREA 2.724000 ;
    PORT
      LAYER Metal2 ;
        RECT 150.040 0.000 150.440 0.400 ;
    END
  END Tile_X0Y0_S4BEG[7]
  PIN Tile_X0Y0_S4BEG[8]
    DIRECTION OUTPUT ;
    USE SIGNAL ;
    ANTENNADIFFAREA 2.724000 ;
    PORT
      LAYER Metal2 ;
        RECT 151.000 0.000 151.400 0.400 ;
    END
  END Tile_X0Y0_S4BEG[8]
  PIN Tile_X0Y0_S4BEG[9]
    DIRECTION OUTPUT ;
    USE SIGNAL ;
    ANTENNADIFFAREA 2.724000 ;
    PORT
      LAYER Metal2 ;
        RECT 151.960 0.000 152.360 0.400 ;
    END
  END Tile_X0Y0_S4BEG[9]
  PIN Tile_X0Y0_SS4BEG[0]
    DIRECTION OUTPUT ;
    USE SIGNAL ;
    ANTENNADIFFAREA 2.724000 ;
    PORT
      LAYER Metal2 ;
        RECT 173.080 0.000 173.480 0.400 ;
    END
  END Tile_X0Y0_SS4BEG[0]
  PIN Tile_X0Y0_SS4BEG[10]
    DIRECTION OUTPUT ;
    USE SIGNAL ;
    ANTENNADIFFAREA 2.724000 ;
    PORT
      LAYER Metal2 ;
        RECT 182.680 0.000 183.080 0.400 ;
    END
  END Tile_X0Y0_SS4BEG[10]
  PIN Tile_X0Y0_SS4BEG[11]
    DIRECTION OUTPUT ;
    USE SIGNAL ;
    ANTENNADIFFAREA 2.724000 ;
    PORT
      LAYER Metal2 ;
        RECT 183.640 0.000 184.040 0.400 ;
    END
  END Tile_X0Y0_SS4BEG[11]
  PIN Tile_X0Y0_SS4BEG[12]
    DIRECTION OUTPUT ;
    USE SIGNAL ;
    ANTENNADIFFAREA 2.724000 ;
    PORT
      LAYER Metal2 ;
        RECT 184.600 0.000 185.000 0.400 ;
    END
  END Tile_X0Y0_SS4BEG[12]
  PIN Tile_X0Y0_SS4BEG[13]
    DIRECTION OUTPUT ;
    USE SIGNAL ;
    ANTENNADIFFAREA 2.724000 ;
    PORT
      LAYER Metal2 ;
        RECT 185.560 0.000 185.960 0.400 ;
    END
  END Tile_X0Y0_SS4BEG[13]
  PIN Tile_X0Y0_SS4BEG[14]
    DIRECTION OUTPUT ;
    USE SIGNAL ;
    ANTENNADIFFAREA 2.724000 ;
    PORT
      LAYER Metal2 ;
        RECT 186.520 0.000 186.920 0.400 ;
    END
  END Tile_X0Y0_SS4BEG[14]
  PIN Tile_X0Y0_SS4BEG[15]
    DIRECTION OUTPUT ;
    USE SIGNAL ;
    ANTENNADIFFAREA 2.724000 ;
    PORT
      LAYER Metal2 ;
        RECT 187.480 0.000 187.880 0.400 ;
    END
  END Tile_X0Y0_SS4BEG[15]
  PIN Tile_X0Y0_SS4BEG[1]
    DIRECTION OUTPUT ;
    USE SIGNAL ;
    ANTENNADIFFAREA 2.724000 ;
    PORT
      LAYER Metal2 ;
        RECT 174.040 0.000 174.440 0.400 ;
    END
  END Tile_X0Y0_SS4BEG[1]
  PIN Tile_X0Y0_SS4BEG[2]
    DIRECTION OUTPUT ;
    USE SIGNAL ;
    ANTENNADIFFAREA 2.724000 ;
    PORT
      LAYER Metal2 ;
        RECT 175.000 0.000 175.400 0.400 ;
    END
  END Tile_X0Y0_SS4BEG[2]
  PIN Tile_X0Y0_SS4BEG[3]
    DIRECTION OUTPUT ;
    USE SIGNAL ;
    ANTENNADIFFAREA 2.724000 ;
    PORT
      LAYER Metal2 ;
        RECT 175.960 0.000 176.360 0.400 ;
    END
  END Tile_X0Y0_SS4BEG[3]
  PIN Tile_X0Y0_SS4BEG[4]
    DIRECTION OUTPUT ;
    USE SIGNAL ;
    ANTENNADIFFAREA 2.724000 ;
    PORT
      LAYER Metal2 ;
        RECT 176.920 0.000 177.320 0.400 ;
    END
  END Tile_X0Y0_SS4BEG[4]
  PIN Tile_X0Y0_SS4BEG[5]
    DIRECTION OUTPUT ;
    USE SIGNAL ;
    ANTENNADIFFAREA 2.724000 ;
    PORT
      LAYER Metal2 ;
        RECT 177.880 0.000 178.280 0.400 ;
    END
  END Tile_X0Y0_SS4BEG[5]
  PIN Tile_X0Y0_SS4BEG[6]
    DIRECTION OUTPUT ;
    USE SIGNAL ;
    ANTENNADIFFAREA 2.724000 ;
    PORT
      LAYER Metal2 ;
        RECT 178.840 0.000 179.240 0.400 ;
    END
  END Tile_X0Y0_SS4BEG[6]
  PIN Tile_X0Y0_SS4BEG[7]
    DIRECTION OUTPUT ;
    USE SIGNAL ;
    ANTENNADIFFAREA 2.724000 ;
    PORT
      LAYER Metal2 ;
        RECT 179.800 0.000 180.200 0.400 ;
    END
  END Tile_X0Y0_SS4BEG[7]
  PIN Tile_X0Y0_SS4BEG[8]
    DIRECTION OUTPUT ;
    USE SIGNAL ;
    ANTENNADIFFAREA 2.724000 ;
    PORT
      LAYER Metal2 ;
        RECT 180.760 0.000 181.160 0.400 ;
    END
  END Tile_X0Y0_SS4BEG[8]
  PIN Tile_X0Y0_SS4BEG[9]
    DIRECTION OUTPUT ;
    USE SIGNAL ;
    ANTENNADIFFAREA 2.724000 ;
    PORT
      LAYER Metal2 ;
        RECT 181.720 0.000 182.120 0.400 ;
    END
  END Tile_X0Y0_SS4BEG[9]
  PIN Tile_X0Y0_UserCLK
    DIRECTION INPUT ;
    USE SIGNAL ;
    ANTENNAGATEAREA 5.983900 ;
    PORT
      LAYER Metal3 ;
        RECT 0.000 1.900 0.400 2.300 ;
    END
  END Tile_X0Y0_UserCLK
  PIN Tile_X1Y0_Ci
    DIRECTION INPUT ;
    USE SIGNAL ;
    PORT
      LAYER Metal2 ;
        RECT 330.520 0.000 330.920 0.400 ;
    END
  END Tile_X1Y0_Ci
  PIN Tile_X1Y0_FrameData_O[0]
    DIRECTION OUTPUT ;
    USE SIGNAL ;
    ANTENNADIFFAREA 2.724000 ;
    PORT
      LAYER Metal3 ;
        RECT 466.160 15.340 466.560 15.740 ;
    END
  END Tile_X1Y0_FrameData_O[0]
  PIN Tile_X1Y0_FrameData_O[10]
    DIRECTION OUTPUT ;
    USE SIGNAL ;
    ANTENNADIFFAREA 2.724000 ;
    PORT
      LAYER Metal3 ;
        RECT 466.160 32.140 466.560 32.540 ;
    END
  END Tile_X1Y0_FrameData_O[10]
  PIN Tile_X1Y0_FrameData_O[11]
    DIRECTION OUTPUT ;
    USE SIGNAL ;
    ANTENNADIFFAREA 2.724000 ;
    PORT
      LAYER Metal3 ;
        RECT 466.160 33.820 466.560 34.220 ;
    END
  END Tile_X1Y0_FrameData_O[11]
  PIN Tile_X1Y0_FrameData_O[12]
    DIRECTION OUTPUT ;
    USE SIGNAL ;
    ANTENNADIFFAREA 2.724000 ;
    PORT
      LAYER Metal3 ;
        RECT 466.160 35.500 466.560 35.900 ;
    END
  END Tile_X1Y0_FrameData_O[12]
  PIN Tile_X1Y0_FrameData_O[13]
    DIRECTION OUTPUT ;
    USE SIGNAL ;
    ANTENNADIFFAREA 2.724000 ;
    PORT
      LAYER Metal3 ;
        RECT 466.160 37.180 466.560 37.580 ;
    END
  END Tile_X1Y0_FrameData_O[13]
  PIN Tile_X1Y0_FrameData_O[14]
    DIRECTION OUTPUT ;
    USE SIGNAL ;
    ANTENNADIFFAREA 2.724000 ;
    PORT
      LAYER Metal3 ;
        RECT 466.160 38.860 466.560 39.260 ;
    END
  END Tile_X1Y0_FrameData_O[14]
  PIN Tile_X1Y0_FrameData_O[15]
    DIRECTION OUTPUT ;
    USE SIGNAL ;
    ANTENNADIFFAREA 2.724000 ;
    PORT
      LAYER Metal3 ;
        RECT 466.160 40.540 466.560 40.940 ;
    END
  END Tile_X1Y0_FrameData_O[15]
  PIN Tile_X1Y0_FrameData_O[16]
    DIRECTION OUTPUT ;
    USE SIGNAL ;
    ANTENNADIFFAREA 2.724000 ;
    PORT
      LAYER Metal3 ;
        RECT 466.160 42.220 466.560 42.620 ;
    END
  END Tile_X1Y0_FrameData_O[16]
  PIN Tile_X1Y0_FrameData_O[17]
    DIRECTION OUTPUT ;
    USE SIGNAL ;
    ANTENNADIFFAREA 2.724000 ;
    PORT
      LAYER Metal3 ;
        RECT 466.160 43.900 466.560 44.300 ;
    END
  END Tile_X1Y0_FrameData_O[17]
  PIN Tile_X1Y0_FrameData_O[18]
    DIRECTION OUTPUT ;
    USE SIGNAL ;
    ANTENNADIFFAREA 2.724000 ;
    PORT
      LAYER Metal3 ;
        RECT 466.160 45.580 466.560 45.980 ;
    END
  END Tile_X1Y0_FrameData_O[18]
  PIN Tile_X1Y0_FrameData_O[19]
    DIRECTION OUTPUT ;
    USE SIGNAL ;
    ANTENNADIFFAREA 2.724000 ;
    PORT
      LAYER Metal3 ;
        RECT 466.160 47.260 466.560 47.660 ;
    END
  END Tile_X1Y0_FrameData_O[19]
  PIN Tile_X1Y0_FrameData_O[1]
    DIRECTION OUTPUT ;
    USE SIGNAL ;
    ANTENNADIFFAREA 2.724000 ;
    PORT
      LAYER Metal3 ;
        RECT 466.160 17.020 466.560 17.420 ;
    END
  END Tile_X1Y0_FrameData_O[1]
  PIN Tile_X1Y0_FrameData_O[20]
    DIRECTION OUTPUT ;
    USE SIGNAL ;
    ANTENNADIFFAREA 2.724000 ;
    PORT
      LAYER Metal3 ;
        RECT 466.160 48.940 466.560 49.340 ;
    END
  END Tile_X1Y0_FrameData_O[20]
  PIN Tile_X1Y0_FrameData_O[21]
    DIRECTION OUTPUT ;
    USE SIGNAL ;
    ANTENNADIFFAREA 2.724000 ;
    PORT
      LAYER Metal3 ;
        RECT 466.160 50.620 466.560 51.020 ;
    END
  END Tile_X1Y0_FrameData_O[21]
  PIN Tile_X1Y0_FrameData_O[22]
    DIRECTION OUTPUT ;
    USE SIGNAL ;
    ANTENNADIFFAREA 2.724000 ;
    PORT
      LAYER Metal3 ;
        RECT 466.160 52.300 466.560 52.700 ;
    END
  END Tile_X1Y0_FrameData_O[22]
  PIN Tile_X1Y0_FrameData_O[23]
    DIRECTION OUTPUT ;
    USE SIGNAL ;
    ANTENNADIFFAREA 2.724000 ;
    PORT
      LAYER Metal3 ;
        RECT 466.160 53.980 466.560 54.380 ;
    END
  END Tile_X1Y0_FrameData_O[23]
  PIN Tile_X1Y0_FrameData_O[24]
    DIRECTION OUTPUT ;
    USE SIGNAL ;
    ANTENNADIFFAREA 2.724000 ;
    PORT
      LAYER Metal3 ;
        RECT 466.160 55.660 466.560 56.060 ;
    END
  END Tile_X1Y0_FrameData_O[24]
  PIN Tile_X1Y0_FrameData_O[25]
    DIRECTION OUTPUT ;
    USE SIGNAL ;
    ANTENNADIFFAREA 2.724000 ;
    PORT
      LAYER Metal3 ;
        RECT 466.160 57.340 466.560 57.740 ;
    END
  END Tile_X1Y0_FrameData_O[25]
  PIN Tile_X1Y0_FrameData_O[26]
    DIRECTION OUTPUT ;
    USE SIGNAL ;
    ANTENNADIFFAREA 2.724000 ;
    PORT
      LAYER Metal3 ;
        RECT 466.160 59.020 466.560 59.420 ;
    END
  END Tile_X1Y0_FrameData_O[26]
  PIN Tile_X1Y0_FrameData_O[27]
    DIRECTION OUTPUT ;
    USE SIGNAL ;
    ANTENNADIFFAREA 2.724000 ;
    PORT
      LAYER Metal3 ;
        RECT 466.160 60.700 466.560 61.100 ;
    END
  END Tile_X1Y0_FrameData_O[27]
  PIN Tile_X1Y0_FrameData_O[28]
    DIRECTION OUTPUT ;
    USE SIGNAL ;
    ANTENNADIFFAREA 2.724000 ;
    PORT
      LAYER Metal3 ;
        RECT 466.160 62.380 466.560 62.780 ;
    END
  END Tile_X1Y0_FrameData_O[28]
  PIN Tile_X1Y0_FrameData_O[29]
    DIRECTION OUTPUT ;
    USE SIGNAL ;
    ANTENNADIFFAREA 2.724000 ;
    PORT
      LAYER Metal3 ;
        RECT 466.160 64.060 466.560 64.460 ;
    END
  END Tile_X1Y0_FrameData_O[29]
  PIN Tile_X1Y0_FrameData_O[2]
    DIRECTION OUTPUT ;
    USE SIGNAL ;
    ANTENNADIFFAREA 2.724000 ;
    PORT
      LAYER Metal3 ;
        RECT 466.160 18.700 466.560 19.100 ;
    END
  END Tile_X1Y0_FrameData_O[2]
  PIN Tile_X1Y0_FrameData_O[30]
    DIRECTION OUTPUT ;
    USE SIGNAL ;
    ANTENNADIFFAREA 2.724000 ;
    PORT
      LAYER Metal3 ;
        RECT 466.160 65.740 466.560 66.140 ;
    END
  END Tile_X1Y0_FrameData_O[30]
  PIN Tile_X1Y0_FrameData_O[31]
    DIRECTION OUTPUT ;
    USE SIGNAL ;
    ANTENNADIFFAREA 2.724000 ;
    PORT
      LAYER Metal3 ;
        RECT 466.160 67.420 466.560 67.820 ;
    END
  END Tile_X1Y0_FrameData_O[31]
  PIN Tile_X1Y0_FrameData_O[3]
    DIRECTION OUTPUT ;
    USE SIGNAL ;
    ANTENNADIFFAREA 2.724000 ;
    PORT
      LAYER Metal3 ;
        RECT 466.160 20.380 466.560 20.780 ;
    END
  END Tile_X1Y0_FrameData_O[3]
  PIN Tile_X1Y0_FrameData_O[4]
    DIRECTION OUTPUT ;
    USE SIGNAL ;
    ANTENNADIFFAREA 2.724000 ;
    PORT
      LAYER Metal3 ;
        RECT 466.160 22.060 466.560 22.460 ;
    END
  END Tile_X1Y0_FrameData_O[4]
  PIN Tile_X1Y0_FrameData_O[5]
    DIRECTION OUTPUT ;
    USE SIGNAL ;
    ANTENNADIFFAREA 2.724000 ;
    PORT
      LAYER Metal3 ;
        RECT 466.160 23.740 466.560 24.140 ;
    END
  END Tile_X1Y0_FrameData_O[5]
  PIN Tile_X1Y0_FrameData_O[6]
    DIRECTION OUTPUT ;
    USE SIGNAL ;
    ANTENNADIFFAREA 2.724000 ;
    PORT
      LAYER Metal3 ;
        RECT 466.160 25.420 466.560 25.820 ;
    END
  END Tile_X1Y0_FrameData_O[6]
  PIN Tile_X1Y0_FrameData_O[7]
    DIRECTION OUTPUT ;
    USE SIGNAL ;
    ANTENNADIFFAREA 2.724000 ;
    PORT
      LAYER Metal3 ;
        RECT 466.160 27.100 466.560 27.500 ;
    END
  END Tile_X1Y0_FrameData_O[7]
  PIN Tile_X1Y0_FrameData_O[8]
    DIRECTION OUTPUT ;
    USE SIGNAL ;
    ANTENNADIFFAREA 2.724000 ;
    PORT
      LAYER Metal3 ;
        RECT 466.160 28.780 466.560 29.180 ;
    END
  END Tile_X1Y0_FrameData_O[8]
  PIN Tile_X1Y0_FrameData_O[9]
    DIRECTION OUTPUT ;
    USE SIGNAL ;
    ANTENNADIFFAREA 2.724000 ;
    PORT
      LAYER Metal3 ;
        RECT 466.160 30.460 466.560 30.860 ;
    END
  END Tile_X1Y0_FrameData_O[9]
  PIN Tile_X1Y0_FrameStrobe[0]
    DIRECTION INPUT ;
    USE SIGNAL ;
    ANTENNAGATEAREA 11.745500 ;
    PORT
      LAYER Metal2 ;
        RECT 438.040 0.000 438.440 0.400 ;
    END
  END Tile_X1Y0_FrameStrobe[0]
  PIN Tile_X1Y0_FrameStrobe[10]
    DIRECTION INPUT ;
    USE SIGNAL ;
    ANTENNAGATEAREA 0.180700 ;
    PORT
      LAYER Metal2 ;
        RECT 447.640 0.000 448.040 0.400 ;
    END
  END Tile_X1Y0_FrameStrobe[10]
  PIN Tile_X1Y0_FrameStrobe[11]
    DIRECTION INPUT ;
    USE SIGNAL ;
    ANTENNAGATEAREA 0.180700 ;
    PORT
      LAYER Metal2 ;
        RECT 448.600 0.000 449.000 0.400 ;
    END
  END Tile_X1Y0_FrameStrobe[11]
  PIN Tile_X1Y0_FrameStrobe[12]
    DIRECTION INPUT ;
    USE SIGNAL ;
    ANTENNAGATEAREA 0.180700 ;
    PORT
      LAYER Metal2 ;
        RECT 449.560 0.000 449.960 0.400 ;
    END
  END Tile_X1Y0_FrameStrobe[12]
  PIN Tile_X1Y0_FrameStrobe[13]
    DIRECTION INPUT ;
    USE SIGNAL ;
    ANTENNAGATEAREA 0.180700 ;
    PORT
      LAYER Metal2 ;
        RECT 450.520 0.000 450.920 0.400 ;
    END
  END Tile_X1Y0_FrameStrobe[13]
  PIN Tile_X1Y0_FrameStrobe[14]
    DIRECTION INPUT ;
    USE SIGNAL ;
    ANTENNAGATEAREA 0.180700 ;
    PORT
      LAYER Metal2 ;
        RECT 451.480 0.000 451.880 0.400 ;
    END
  END Tile_X1Y0_FrameStrobe[14]
  PIN Tile_X1Y0_FrameStrobe[15]
    DIRECTION INPUT ;
    USE SIGNAL ;
    ANTENNAGATEAREA 0.180700 ;
    PORT
      LAYER Metal2 ;
        RECT 452.440 0.000 452.840 0.400 ;
    END
  END Tile_X1Y0_FrameStrobe[15]
  PIN Tile_X1Y0_FrameStrobe[16]
    DIRECTION INPUT ;
    USE SIGNAL ;
    ANTENNAGATEAREA 0.180700 ;
    PORT
      LAYER Metal2 ;
        RECT 453.400 0.000 453.800 0.400 ;
    END
  END Tile_X1Y0_FrameStrobe[16]
  PIN Tile_X1Y0_FrameStrobe[17]
    DIRECTION INPUT ;
    USE SIGNAL ;
    ANTENNAGATEAREA 0.180700 ;
    PORT
      LAYER Metal2 ;
        RECT 454.360 0.000 454.760 0.400 ;
    END
  END Tile_X1Y0_FrameStrobe[17]
  PIN Tile_X1Y0_FrameStrobe[18]
    DIRECTION INPUT ;
    USE SIGNAL ;
    ANTENNAGATEAREA 0.180700 ;
    PORT
      LAYER Metal2 ;
        RECT 455.320 0.000 455.720 0.400 ;
    END
  END Tile_X1Y0_FrameStrobe[18]
  PIN Tile_X1Y0_FrameStrobe[19]
    DIRECTION INPUT ;
    USE SIGNAL ;
    ANTENNAGATEAREA 0.180700 ;
    PORT
      LAYER Metal2 ;
        RECT 456.280 0.000 456.680 0.400 ;
    END
  END Tile_X1Y0_FrameStrobe[19]
  PIN Tile_X1Y0_FrameStrobe[1]
    DIRECTION INPUT ;
    USE SIGNAL ;
    ANTENNAGATEAREA 11.745500 ;
    PORT
      LAYER Metal2 ;
        RECT 439.000 0.000 439.400 0.400 ;
    END
  END Tile_X1Y0_FrameStrobe[1]
  PIN Tile_X1Y0_FrameStrobe[2]
    DIRECTION INPUT ;
    USE SIGNAL ;
    ANTENNAGATEAREA 11.745500 ;
    PORT
      LAYER Metal2 ;
        RECT 439.960 0.000 440.360 0.400 ;
    END
  END Tile_X1Y0_FrameStrobe[2]
  PIN Tile_X1Y0_FrameStrobe[3]
    DIRECTION INPUT ;
    USE SIGNAL ;
    ANTENNAGATEAREA 6.324500 ;
    PORT
      LAYER Metal2 ;
        RECT 440.920 0.000 441.320 0.400 ;
    END
  END Tile_X1Y0_FrameStrobe[3]
  PIN Tile_X1Y0_FrameStrobe[4]
    DIRECTION INPUT ;
    USE SIGNAL ;
    ANTENNAGATEAREA 0.180700 ;
    PORT
      LAYER Metal2 ;
        RECT 441.880 0.000 442.280 0.400 ;
    END
  END Tile_X1Y0_FrameStrobe[4]
  PIN Tile_X1Y0_FrameStrobe[5]
    DIRECTION INPUT ;
    USE SIGNAL ;
    ANTENNAGATEAREA 0.180700 ;
    PORT
      LAYER Metal2 ;
        RECT 442.840 0.000 443.240 0.400 ;
    END
  END Tile_X1Y0_FrameStrobe[5]
  PIN Tile_X1Y0_FrameStrobe[6]
    DIRECTION INPUT ;
    USE SIGNAL ;
    ANTENNAGATEAREA 0.180700 ;
    PORT
      LAYER Metal2 ;
        RECT 443.800 0.000 444.200 0.400 ;
    END
  END Tile_X1Y0_FrameStrobe[6]
  PIN Tile_X1Y0_FrameStrobe[7]
    DIRECTION INPUT ;
    USE SIGNAL ;
    ANTENNAGATEAREA 0.180700 ;
    PORT
      LAYER Metal2 ;
        RECT 444.760 0.000 445.160 0.400 ;
    END
  END Tile_X1Y0_FrameStrobe[7]
  PIN Tile_X1Y0_FrameStrobe[8]
    DIRECTION INPUT ;
    USE SIGNAL ;
    ANTENNAGATEAREA 0.180700 ;
    PORT
      LAYER Metal2 ;
        RECT 445.720 0.000 446.120 0.400 ;
    END
  END Tile_X1Y0_FrameStrobe[8]
  PIN Tile_X1Y0_FrameStrobe[9]
    DIRECTION INPUT ;
    USE SIGNAL ;
    ANTENNAGATEAREA 0.180700 ;
    PORT
      LAYER Metal2 ;
        RECT 446.680 0.000 447.080 0.400 ;
    END
  END Tile_X1Y0_FrameStrobe[9]
  PIN Tile_X1Y0_FrameStrobe_O[0]
    DIRECTION OUTPUT ;
    USE SIGNAL ;
    ANTENNADIFFAREA 2.724000 ;
    PORT
      LAYER Metal2 ;
        RECT 241.240 78.980 241.640 79.380 ;
    END
  END Tile_X1Y0_FrameStrobe_O[0]
  PIN Tile_X1Y0_FrameStrobe_O[10]
    DIRECTION OUTPUT ;
    USE SIGNAL ;
    ANTENNADIFFAREA 2.724000 ;
    PORT
      LAYER Metal2 ;
        RECT 289.240 78.980 289.640 79.380 ;
    END
  END Tile_X1Y0_FrameStrobe_O[10]
  PIN Tile_X1Y0_FrameStrobe_O[11]
    DIRECTION OUTPUT ;
    USE SIGNAL ;
    ANTENNADIFFAREA 2.724000 ;
    PORT
      LAYER Metal2 ;
        RECT 294.040 78.980 294.440 79.380 ;
    END
  END Tile_X1Y0_FrameStrobe_O[11]
  PIN Tile_X1Y0_FrameStrobe_O[12]
    DIRECTION OUTPUT ;
    USE SIGNAL ;
    ANTENNADIFFAREA 2.724000 ;
    PORT
      LAYER Metal2 ;
        RECT 298.840 78.980 299.240 79.380 ;
    END
  END Tile_X1Y0_FrameStrobe_O[12]
  PIN Tile_X1Y0_FrameStrobe_O[13]
    DIRECTION OUTPUT ;
    USE SIGNAL ;
    ANTENNADIFFAREA 2.724000 ;
    PORT
      LAYER Metal2 ;
        RECT 303.640 78.980 304.040 79.380 ;
    END
  END Tile_X1Y0_FrameStrobe_O[13]
  PIN Tile_X1Y0_FrameStrobe_O[14]
    DIRECTION OUTPUT ;
    USE SIGNAL ;
    ANTENNADIFFAREA 2.724000 ;
    PORT
      LAYER Metal2 ;
        RECT 308.440 78.980 308.840 79.380 ;
    END
  END Tile_X1Y0_FrameStrobe_O[14]
  PIN Tile_X1Y0_FrameStrobe_O[15]
    DIRECTION OUTPUT ;
    USE SIGNAL ;
    ANTENNADIFFAREA 2.724000 ;
    PORT
      LAYER Metal2 ;
        RECT 313.240 78.980 313.640 79.380 ;
    END
  END Tile_X1Y0_FrameStrobe_O[15]
  PIN Tile_X1Y0_FrameStrobe_O[16]
    DIRECTION OUTPUT ;
    USE SIGNAL ;
    ANTENNADIFFAREA 2.724000 ;
    PORT
      LAYER Metal2 ;
        RECT 318.040 78.980 318.440 79.380 ;
    END
  END Tile_X1Y0_FrameStrobe_O[16]
  PIN Tile_X1Y0_FrameStrobe_O[17]
    DIRECTION OUTPUT ;
    USE SIGNAL ;
    ANTENNADIFFAREA 2.724000 ;
    PORT
      LAYER Metal2 ;
        RECT 322.840 78.980 323.240 79.380 ;
    END
  END Tile_X1Y0_FrameStrobe_O[17]
  PIN Tile_X1Y0_FrameStrobe_O[18]
    DIRECTION OUTPUT ;
    USE SIGNAL ;
    ANTENNADIFFAREA 2.724000 ;
    PORT
      LAYER Metal2 ;
        RECT 327.640 78.980 328.040 79.380 ;
    END
  END Tile_X1Y0_FrameStrobe_O[18]
  PIN Tile_X1Y0_FrameStrobe_O[19]
    DIRECTION OUTPUT ;
    USE SIGNAL ;
    ANTENNADIFFAREA 2.724000 ;
    PORT
      LAYER Metal2 ;
        RECT 332.440 78.980 332.840 79.380 ;
    END
  END Tile_X1Y0_FrameStrobe_O[19]
  PIN Tile_X1Y0_FrameStrobe_O[1]
    DIRECTION OUTPUT ;
    USE SIGNAL ;
    ANTENNADIFFAREA 2.724000 ;
    PORT
      LAYER Metal2 ;
        RECT 246.040 78.980 246.440 79.380 ;
    END
  END Tile_X1Y0_FrameStrobe_O[1]
  PIN Tile_X1Y0_FrameStrobe_O[2]
    DIRECTION OUTPUT ;
    USE SIGNAL ;
    ANTENNADIFFAREA 2.724000 ;
    PORT
      LAYER Metal2 ;
        RECT 250.840 78.980 251.240 79.380 ;
    END
  END Tile_X1Y0_FrameStrobe_O[2]
  PIN Tile_X1Y0_FrameStrobe_O[3]
    DIRECTION OUTPUT ;
    USE SIGNAL ;
    ANTENNADIFFAREA 2.724000 ;
    PORT
      LAYER Metal2 ;
        RECT 255.640 78.980 256.040 79.380 ;
    END
  END Tile_X1Y0_FrameStrobe_O[3]
  PIN Tile_X1Y0_FrameStrobe_O[4]
    DIRECTION OUTPUT ;
    USE SIGNAL ;
    ANTENNADIFFAREA 2.724000 ;
    PORT
      LAYER Metal2 ;
        RECT 260.440 78.980 260.840 79.380 ;
    END
  END Tile_X1Y0_FrameStrobe_O[4]
  PIN Tile_X1Y0_FrameStrobe_O[5]
    DIRECTION OUTPUT ;
    USE SIGNAL ;
    ANTENNADIFFAREA 2.724000 ;
    PORT
      LAYER Metal2 ;
        RECT 265.240 78.980 265.640 79.380 ;
    END
  END Tile_X1Y0_FrameStrobe_O[5]
  PIN Tile_X1Y0_FrameStrobe_O[6]
    DIRECTION OUTPUT ;
    USE SIGNAL ;
    ANTENNADIFFAREA 2.724000 ;
    PORT
      LAYER Metal2 ;
        RECT 270.040 78.980 270.440 79.380 ;
    END
  END Tile_X1Y0_FrameStrobe_O[6]
  PIN Tile_X1Y0_FrameStrobe_O[7]
    DIRECTION OUTPUT ;
    USE SIGNAL ;
    ANTENNADIFFAREA 2.724000 ;
    PORT
      LAYER Metal2 ;
        RECT 274.840 78.980 275.240 79.380 ;
    END
  END Tile_X1Y0_FrameStrobe_O[7]
  PIN Tile_X1Y0_FrameStrobe_O[8]
    DIRECTION OUTPUT ;
    USE SIGNAL ;
    ANTENNADIFFAREA 2.724000 ;
    PORT
      LAYER Metal2 ;
        RECT 279.640 78.980 280.040 79.380 ;
    END
  END Tile_X1Y0_FrameStrobe_O[8]
  PIN Tile_X1Y0_FrameStrobe_O[9]
    DIRECTION OUTPUT ;
    USE SIGNAL ;
    ANTENNADIFFAREA 2.724000 ;
    PORT
      LAYER Metal2 ;
        RECT 284.440 78.980 284.840 79.380 ;
    END
  END Tile_X1Y0_FrameStrobe_O[9]
  PIN Tile_X1Y0_N1END[0]
    DIRECTION INPUT ;
    USE SIGNAL ;
    ANTENNAGATEAREA 0.820300 ;
    PORT
      LAYER Metal2 ;
        RECT 234.520 0.000 234.920 0.400 ;
    END
  END Tile_X1Y0_N1END[0]
  PIN Tile_X1Y0_N1END[1]
    DIRECTION INPUT ;
    USE SIGNAL ;
    ANTENNAGATEAREA 0.820300 ;
    PORT
      LAYER Metal2 ;
        RECT 236.440 0.000 236.840 0.400 ;
    END
  END Tile_X1Y0_N1END[1]
  PIN Tile_X1Y0_N1END[2]
    DIRECTION INPUT ;
    USE SIGNAL ;
    ANTENNAGATEAREA 0.607100 ;
    PORT
      LAYER Metal2 ;
        RECT 238.360 0.000 238.760 0.400 ;
    END
  END Tile_X1Y0_N1END[2]
  PIN Tile_X1Y0_N1END[3]
    DIRECTION INPUT ;
    USE SIGNAL ;
    ANTENNAGATEAREA 0.607100 ;
    PORT
      LAYER Metal2 ;
        RECT 240.280 0.000 240.680 0.400 ;
    END
  END Tile_X1Y0_N1END[3]
  PIN Tile_X1Y0_N2END[0]
    DIRECTION INPUT ;
    USE SIGNAL ;
    ANTENNAGATEAREA 0.852800 ;
    PORT
      LAYER Metal2 ;
        RECT 259.480 0.000 259.880 0.400 ;
    END
  END Tile_X1Y0_N2END[0]
  PIN Tile_X1Y0_N2END[1]
    DIRECTION INPUT ;
    USE SIGNAL ;
    ANTENNAGATEAREA 0.852800 ;
    PORT
      LAYER Metal2 ;
        RECT 260.440 0.000 260.840 0.400 ;
    END
  END Tile_X1Y0_N2END[1]
  PIN Tile_X1Y0_N2END[2]
    DIRECTION INPUT ;
    USE SIGNAL ;
    ANTENNAGATEAREA 1.066000 ;
    PORT
      LAYER Metal2 ;
        RECT 261.400 0.000 261.800 0.400 ;
    END
  END Tile_X1Y0_N2END[2]
  PIN Tile_X1Y0_N2END[3]
    DIRECTION INPUT ;
    USE SIGNAL ;
    ANTENNAGATEAREA 1.066000 ;
    PORT
      LAYER Metal2 ;
        RECT 262.360 0.000 262.760 0.400 ;
    END
  END Tile_X1Y0_N2END[3]
  PIN Tile_X1Y0_N2END[4]
    DIRECTION INPUT ;
    USE SIGNAL ;
    ANTENNAGATEAREA 0.852800 ;
    PORT
      LAYER Metal2 ;
        RECT 263.320 0.000 263.720 0.400 ;
    END
  END Tile_X1Y0_N2END[4]
  PIN Tile_X1Y0_N2END[5]
    DIRECTION INPUT ;
    USE SIGNAL ;
    ANTENNAGATEAREA 0.852800 ;
    PORT
      LAYER Metal2 ;
        RECT 264.280 0.000 264.680 0.400 ;
    END
  END Tile_X1Y0_N2END[5]
  PIN Tile_X1Y0_N2END[6]
    DIRECTION INPUT ;
    USE SIGNAL ;
    ANTENNAGATEAREA 0.852800 ;
    PORT
      LAYER Metal2 ;
        RECT 265.240 0.000 265.640 0.400 ;
    END
  END Tile_X1Y0_N2END[6]
  PIN Tile_X1Y0_N2END[7]
    DIRECTION INPUT ;
    USE SIGNAL ;
    ANTENNAGATEAREA 0.852800 ;
    PORT
      LAYER Metal2 ;
        RECT 266.200 0.000 266.600 0.400 ;
    END
  END Tile_X1Y0_N2END[7]
  PIN Tile_X1Y0_N2MID[0]
    DIRECTION INPUT ;
    USE SIGNAL ;
    ANTENNAGATEAREA 1.033500 ;
    PORT
      LAYER Metal2 ;
        RECT 245.080 0.000 245.480 0.400 ;
    END
  END Tile_X1Y0_N2MID[0]
  PIN Tile_X1Y0_N2MID[1]
    DIRECTION INPUT ;
    USE SIGNAL ;
    ANTENNAGATEAREA 1.033500 ;
    PORT
      LAYER Metal2 ;
        RECT 246.040 0.000 246.440 0.400 ;
    END
  END Tile_X1Y0_N2MID[1]
  PIN Tile_X1Y0_N2MID[2]
    DIRECTION INPUT ;
    USE SIGNAL ;
    ANTENNAGATEAREA 1.033500 ;
    PORT
      LAYER Metal2 ;
        RECT 247.000 0.000 247.400 0.400 ;
    END
  END Tile_X1Y0_N2MID[2]
  PIN Tile_X1Y0_N2MID[3]
    DIRECTION INPUT ;
    USE SIGNAL ;
    ANTENNAGATEAREA 1.033500 ;
    PORT
      LAYER Metal2 ;
        RECT 247.960 0.000 248.360 0.400 ;
    END
  END Tile_X1Y0_N2MID[3]
  PIN Tile_X1Y0_N2MID[4]
    DIRECTION INPUT ;
    USE SIGNAL ;
    ANTENNAGATEAREA 1.033500 ;
    PORT
      LAYER Metal2 ;
        RECT 248.920 0.000 249.320 0.400 ;
    END
  END Tile_X1Y0_N2MID[4]
  PIN Tile_X1Y0_N2MID[5]
    DIRECTION INPUT ;
    USE SIGNAL ;
    ANTENNAGATEAREA 1.033500 ;
    PORT
      LAYER Metal2 ;
        RECT 249.880 0.000 250.280 0.400 ;
    END
  END Tile_X1Y0_N2MID[5]
  PIN Tile_X1Y0_N2MID[6]
    DIRECTION INPUT ;
    USE SIGNAL ;
    ANTENNAGATEAREA 1.033500 ;
    PORT
      LAYER Metal2 ;
        RECT 250.840 0.000 251.240 0.400 ;
    END
  END Tile_X1Y0_N2MID[6]
  PIN Tile_X1Y0_N2MID[7]
    DIRECTION INPUT ;
    USE SIGNAL ;
    ANTENNAGATEAREA 1.033500 ;
    PORT
      LAYER Metal2 ;
        RECT 251.800 0.000 252.200 0.400 ;
    END
  END Tile_X1Y0_N2MID[7]
  PIN Tile_X1Y0_N4END[0]
    DIRECTION INPUT ;
    USE SIGNAL ;
    ANTENNAGATEAREA 0.426400 ;
    PORT
      LAYER Metal2 ;
        RECT 277.720 0.000 278.120 0.400 ;
    END
  END Tile_X1Y0_N4END[0]
  PIN Tile_X1Y0_N4END[10]
    DIRECTION INPUT ;
    USE SIGNAL ;
    ANTENNAGATEAREA 0.639600 ;
    PORT
      LAYER Metal2 ;
        RECT 287.320 0.000 287.720 0.400 ;
    END
  END Tile_X1Y0_N4END[10]
  PIN Tile_X1Y0_N4END[11]
    DIRECTION INPUT ;
    USE SIGNAL ;
    ANTENNAGATEAREA 0.639600 ;
    PORT
      LAYER Metal2 ;
        RECT 288.280 0.000 288.680 0.400 ;
    END
  END Tile_X1Y0_N4END[11]
  PIN Tile_X1Y0_N4END[12]
    DIRECTION INPUT ;
    USE SIGNAL ;
    ANTENNAGATEAREA 0.639600 ;
    PORT
      LAYER Metal2 ;
        RECT 289.240 0.000 289.640 0.400 ;
    END
  END Tile_X1Y0_N4END[12]
  PIN Tile_X1Y0_N4END[13]
    DIRECTION INPUT ;
    USE SIGNAL ;
    ANTENNAGATEAREA 0.639600 ;
    PORT
      LAYER Metal2 ;
        RECT 290.200 0.000 290.600 0.400 ;
    END
  END Tile_X1Y0_N4END[13]
  PIN Tile_X1Y0_N4END[14]
    DIRECTION INPUT ;
    USE SIGNAL ;
    ANTENNAGATEAREA 0.852800 ;
    PORT
      LAYER Metal2 ;
        RECT 291.160 0.000 291.560 0.400 ;
    END
  END Tile_X1Y0_N4END[14]
  PIN Tile_X1Y0_N4END[15]
    DIRECTION INPUT ;
    USE SIGNAL ;
    ANTENNAGATEAREA 0.852800 ;
    PORT
      LAYER Metal2 ;
        RECT 292.120 0.000 292.520 0.400 ;
    END
  END Tile_X1Y0_N4END[15]
  PIN Tile_X1Y0_N4END[1]
    DIRECTION INPUT ;
    USE SIGNAL ;
    ANTENNAGATEAREA 0.426400 ;
    PORT
      LAYER Metal2 ;
        RECT 278.680 0.000 279.080 0.400 ;
    END
  END Tile_X1Y0_N4END[1]
  PIN Tile_X1Y0_N4END[2]
    DIRECTION INPUT ;
    USE SIGNAL ;
    ANTENNAGATEAREA 0.426400 ;
    PORT
      LAYER Metal2 ;
        RECT 279.640 0.000 280.040 0.400 ;
    END
  END Tile_X1Y0_N4END[2]
  PIN Tile_X1Y0_N4END[3]
    DIRECTION INPUT ;
    USE SIGNAL ;
    ANTENNAGATEAREA 0.426400 ;
    PORT
      LAYER Metal2 ;
        RECT 280.600 0.000 281.000 0.400 ;
    END
  END Tile_X1Y0_N4END[3]
  PIN Tile_X1Y0_N4END[4]
    DIRECTION INPUT ;
    USE SIGNAL ;
    ANTENNAGATEAREA 0.426400 ;
    PORT
      LAYER Metal2 ;
        RECT 281.560 0.000 281.960 0.400 ;
    END
  END Tile_X1Y0_N4END[4]
  PIN Tile_X1Y0_N4END[5]
    DIRECTION INPUT ;
    USE SIGNAL ;
    ANTENNAGATEAREA 0.426400 ;
    ANTENNADIFFAREA 8.061600 ;
    PORT
      LAYER Metal2 ;
        RECT 282.520 0.000 282.920 0.400 ;
    END
  END Tile_X1Y0_N4END[5]
  PIN Tile_X1Y0_N4END[6]
    DIRECTION INPUT ;
    USE SIGNAL ;
    ANTENNAGATEAREA 0.426400 ;
    PORT
      LAYER Metal2 ;
        RECT 283.480 0.000 283.880 0.400 ;
    END
  END Tile_X1Y0_N4END[6]
  PIN Tile_X1Y0_N4END[7]
    DIRECTION INPUT ;
    USE SIGNAL ;
    ANTENNAGATEAREA 0.426400 ;
    PORT
      LAYER Metal2 ;
        RECT 284.440 0.000 284.840 0.400 ;
    END
  END Tile_X1Y0_N4END[7]
  PIN Tile_X1Y0_N4END[8]
    DIRECTION INPUT ;
    USE SIGNAL ;
    ANTENNAGATEAREA 0.639600 ;
    PORT
      LAYER Metal2 ;
        RECT 285.400 0.000 285.800 0.400 ;
    END
  END Tile_X1Y0_N4END[8]
  PIN Tile_X1Y0_N4END[9]
    DIRECTION INPUT ;
    USE SIGNAL ;
    ANTENNAGATEAREA 0.639600 ;
    PORT
      LAYER Metal2 ;
        RECT 286.360 0.000 286.760 0.400 ;
    END
  END Tile_X1Y0_N4END[9]
  PIN Tile_X1Y0_NN4END[0]
    DIRECTION INPUT ;
    USE SIGNAL ;
    ANTENNAGATEAREA 0.426400 ;
    PORT
      LAYER Metal2 ;
        RECT 307.480 0.000 307.880 0.400 ;
    END
  END Tile_X1Y0_NN4END[0]
  PIN Tile_X1Y0_NN4END[10]
    DIRECTION INPUT ;
    USE SIGNAL ;
    ANTENNAGATEAREA 0.639600 ;
    PORT
      LAYER Metal2 ;
        RECT 317.080 0.000 317.480 0.400 ;
    END
  END Tile_X1Y0_NN4END[10]
  PIN Tile_X1Y0_NN4END[11]
    DIRECTION INPUT ;
    USE SIGNAL ;
    ANTENNAGATEAREA 0.639600 ;
    PORT
      LAYER Metal2 ;
        RECT 318.040 0.000 318.440 0.400 ;
    END
  END Tile_X1Y0_NN4END[11]
  PIN Tile_X1Y0_NN4END[12]
    DIRECTION INPUT ;
    USE SIGNAL ;
    ANTENNAGATEAREA 0.639600 ;
    PORT
      LAYER Metal2 ;
        RECT 319.000 0.000 319.400 0.400 ;
    END
  END Tile_X1Y0_NN4END[12]
  PIN Tile_X1Y0_NN4END[13]
    DIRECTION INPUT ;
    USE SIGNAL ;
    ANTENNAGATEAREA 0.639600 ;
    PORT
      LAYER Metal2 ;
        RECT 319.960 0.000 320.360 0.400 ;
    END
  END Tile_X1Y0_NN4END[13]
  PIN Tile_X1Y0_NN4END[14]
    DIRECTION INPUT ;
    USE SIGNAL ;
    ANTENNAGATEAREA 0.852800 ;
    PORT
      LAYER Metal2 ;
        RECT 320.920 0.000 321.320 0.400 ;
    END
  END Tile_X1Y0_NN4END[14]
  PIN Tile_X1Y0_NN4END[15]
    DIRECTION INPUT ;
    USE SIGNAL ;
    ANTENNAGATEAREA 0.852800 ;
    PORT
      LAYER Metal2 ;
        RECT 321.880 0.000 322.280 0.400 ;
    END
  END Tile_X1Y0_NN4END[15]
  PIN Tile_X1Y0_NN4END[1]
    DIRECTION INPUT ;
    USE SIGNAL ;
    ANTENNAGATEAREA 0.426400 ;
    PORT
      LAYER Metal2 ;
        RECT 308.440 0.000 308.840 0.400 ;
    END
  END Tile_X1Y0_NN4END[1]
  PIN Tile_X1Y0_NN4END[2]
    DIRECTION INPUT ;
    USE SIGNAL ;
    ANTENNAGATEAREA 0.426400 ;
    ANTENNADIFFAREA 8.061600 ;
    PORT
      LAYER Metal2 ;
        RECT 309.400 0.000 309.800 0.400 ;
    END
  END Tile_X1Y0_NN4END[2]
  PIN Tile_X1Y0_NN4END[3]
    DIRECTION INPUT ;
    USE SIGNAL ;
    ANTENNAGATEAREA 0.426400 ;
    PORT
      LAYER Metal2 ;
        RECT 310.360 0.000 310.760 0.400 ;
    END
  END Tile_X1Y0_NN4END[3]
  PIN Tile_X1Y0_NN4END[4]
    DIRECTION INPUT ;
    USE SIGNAL ;
    ANTENNAGATEAREA 0.426400 ;
    PORT
      LAYER Metal2 ;
        RECT 311.320 0.000 311.720 0.400 ;
    END
  END Tile_X1Y0_NN4END[4]
  PIN Tile_X1Y0_NN4END[5]
    DIRECTION INPUT ;
    USE SIGNAL ;
    ANTENNAGATEAREA 0.426400 ;
    ANTENNADIFFAREA 8.061600 ;
    PORT
      LAYER Metal2 ;
        RECT 312.280 0.000 312.680 0.400 ;
    END
  END Tile_X1Y0_NN4END[5]
  PIN Tile_X1Y0_NN4END[6]
    DIRECTION INPUT ;
    USE SIGNAL ;
    ANTENNAGATEAREA 0.426400 ;
    PORT
      LAYER Metal2 ;
        RECT 313.240 0.000 313.640 0.400 ;
    END
  END Tile_X1Y0_NN4END[6]
  PIN Tile_X1Y0_NN4END[7]
    DIRECTION INPUT ;
    USE SIGNAL ;
    ANTENNAGATEAREA 0.426400 ;
    PORT
      LAYER Metal2 ;
        RECT 314.200 0.000 314.600 0.400 ;
    END
  END Tile_X1Y0_NN4END[7]
  PIN Tile_X1Y0_NN4END[8]
    DIRECTION INPUT ;
    USE SIGNAL ;
    ANTENNAGATEAREA 0.639600 ;
    PORT
      LAYER Metal2 ;
        RECT 315.160 0.000 315.560 0.400 ;
    END
  END Tile_X1Y0_NN4END[8]
  PIN Tile_X1Y0_NN4END[9]
    DIRECTION INPUT ;
    USE SIGNAL ;
    ANTENNAGATEAREA 0.639600 ;
    PORT
      LAYER Metal2 ;
        RECT 316.120 0.000 316.520 0.400 ;
    END
  END Tile_X1Y0_NN4END[9]
  PIN Tile_X1Y0_S1BEG[0]
    DIRECTION OUTPUT ;
    USE SIGNAL ;
    ANTENNADIFFAREA 2.724000 ;
    PORT
      LAYER Metal2 ;
        RECT 332.440 0.000 332.840 0.400 ;
    END
  END Tile_X1Y0_S1BEG[0]
  PIN Tile_X1Y0_S1BEG[1]
    DIRECTION OUTPUT ;
    USE SIGNAL ;
    ANTENNADIFFAREA 2.724000 ;
    PORT
      LAYER Metal2 ;
        RECT 334.360 0.000 334.760 0.400 ;
    END
  END Tile_X1Y0_S1BEG[1]
  PIN Tile_X1Y0_S1BEG[2]
    DIRECTION OUTPUT ;
    USE SIGNAL ;
    ANTENNADIFFAREA 2.724000 ;
    PORT
      LAYER Metal2 ;
        RECT 336.280 0.000 336.680 0.400 ;
    END
  END Tile_X1Y0_S1BEG[2]
  PIN Tile_X1Y0_S1BEG[3]
    DIRECTION OUTPUT ;
    USE SIGNAL ;
    ANTENNADIFFAREA 2.724000 ;
    PORT
      LAYER Metal2 ;
        RECT 338.200 0.000 338.600 0.400 ;
    END
  END Tile_X1Y0_S1BEG[3]
  PIN Tile_X1Y0_S2BEG[0]
    DIRECTION OUTPUT ;
    USE SIGNAL ;
    ANTENNADIFFAREA 2.724000 ;
    PORT
      LAYER Metal2 ;
        RECT 340.120 0.000 340.520 0.400 ;
    END
  END Tile_X1Y0_S2BEG[0]
  PIN Tile_X1Y0_S2BEG[1]
    DIRECTION OUTPUT ;
    USE SIGNAL ;
    ANTENNADIFFAREA 2.724000 ;
    PORT
      LAYER Metal2 ;
        RECT 342.040 0.000 342.440 0.400 ;
    END
  END Tile_X1Y0_S2BEG[1]
  PIN Tile_X1Y0_S2BEG[2]
    DIRECTION OUTPUT ;
    USE SIGNAL ;
    ANTENNADIFFAREA 2.724000 ;
    PORT
      LAYER Metal2 ;
        RECT 343.960 0.000 344.360 0.400 ;
    END
  END Tile_X1Y0_S2BEG[2]
  PIN Tile_X1Y0_S2BEG[3]
    DIRECTION OUTPUT ;
    USE SIGNAL ;
    ANTENNADIFFAREA 2.724000 ;
    PORT
      LAYER Metal2 ;
        RECT 345.880 0.000 346.280 0.400 ;
    END
  END Tile_X1Y0_S2BEG[3]
  PIN Tile_X1Y0_S2BEG[4]
    DIRECTION OUTPUT ;
    USE SIGNAL ;
    ANTENNADIFFAREA 2.724000 ;
    PORT
      LAYER Metal2 ;
        RECT 347.800 0.000 348.200 0.400 ;
    END
  END Tile_X1Y0_S2BEG[4]
  PIN Tile_X1Y0_S2BEG[5]
    DIRECTION OUTPUT ;
    USE SIGNAL ;
    ANTENNADIFFAREA 2.724000 ;
    PORT
      LAYER Metal2 ;
        RECT 349.720 0.000 350.120 0.400 ;
    END
  END Tile_X1Y0_S2BEG[5]
  PIN Tile_X1Y0_S2BEG[6]
    DIRECTION OUTPUT ;
    USE SIGNAL ;
    ANTENNADIFFAREA 2.724000 ;
    PORT
      LAYER Metal2 ;
        RECT 351.640 0.000 352.040 0.400 ;
    END
  END Tile_X1Y0_S2BEG[6]
  PIN Tile_X1Y0_S2BEG[7]
    DIRECTION OUTPUT ;
    USE SIGNAL ;
    ANTENNADIFFAREA 2.724000 ;
    PORT
      LAYER Metal2 ;
        RECT 353.560 0.000 353.960 0.400 ;
    END
  END Tile_X1Y0_S2BEG[7]
  PIN Tile_X1Y0_S2BEGb[0]
    DIRECTION OUTPUT ;
    USE SIGNAL ;
    ANTENNADIFFAREA 2.724000 ;
    PORT
      LAYER Metal2 ;
        RECT 358.360 0.000 358.760 0.400 ;
    END
  END Tile_X1Y0_S2BEGb[0]
  PIN Tile_X1Y0_S2BEGb[1]
    DIRECTION OUTPUT ;
    USE SIGNAL ;
    ANTENNADIFFAREA 2.724000 ;
    PORT
      LAYER Metal2 ;
        RECT 359.320 0.000 359.720 0.400 ;
    END
  END Tile_X1Y0_S2BEGb[1]
  PIN Tile_X1Y0_S2BEGb[2]
    DIRECTION OUTPUT ;
    USE SIGNAL ;
    ANTENNADIFFAREA 2.724000 ;
    PORT
      LAYER Metal2 ;
        RECT 360.280 0.000 360.680 0.400 ;
    END
  END Tile_X1Y0_S2BEGb[2]
  PIN Tile_X1Y0_S2BEGb[3]
    DIRECTION OUTPUT ;
    USE SIGNAL ;
    ANTENNADIFFAREA 2.724000 ;
    PORT
      LAYER Metal2 ;
        RECT 361.240 0.000 361.640 0.400 ;
    END
  END Tile_X1Y0_S2BEGb[3]
  PIN Tile_X1Y0_S2BEGb[4]
    DIRECTION OUTPUT ;
    USE SIGNAL ;
    ANTENNADIFFAREA 2.724000 ;
    PORT
      LAYER Metal2 ;
        RECT 362.200 0.000 362.600 0.400 ;
    END
  END Tile_X1Y0_S2BEGb[4]
  PIN Tile_X1Y0_S2BEGb[5]
    DIRECTION OUTPUT ;
    USE SIGNAL ;
    ANTENNADIFFAREA 2.724000 ;
    PORT
      LAYER Metal2 ;
        RECT 363.160 0.000 363.560 0.400 ;
    END
  END Tile_X1Y0_S2BEGb[5]
  PIN Tile_X1Y0_S2BEGb[6]
    DIRECTION OUTPUT ;
    USE SIGNAL ;
    ANTENNADIFFAREA 2.724000 ;
    PORT
      LAYER Metal2 ;
        RECT 364.120 0.000 364.520 0.400 ;
    END
  END Tile_X1Y0_S2BEGb[6]
  PIN Tile_X1Y0_S2BEGb[7]
    DIRECTION OUTPUT ;
    USE SIGNAL ;
    ANTENNADIFFAREA 2.724000 ;
    PORT
      LAYER Metal2 ;
        RECT 365.080 0.000 365.480 0.400 ;
    END
  END Tile_X1Y0_S2BEGb[7]
  PIN Tile_X1Y0_S4BEG[0]
    DIRECTION OUTPUT ;
    USE SIGNAL ;
    ANTENNADIFFAREA 2.724000 ;
    PORT
      LAYER Metal2 ;
        RECT 376.600 0.000 377.000 0.400 ;
    END
  END Tile_X1Y0_S4BEG[0]
  PIN Tile_X1Y0_S4BEG[10]
    DIRECTION OUTPUT ;
    USE SIGNAL ;
    ANTENNADIFFAREA 2.724000 ;
    PORT
      LAYER Metal2 ;
        RECT 386.200 0.000 386.600 0.400 ;
    END
  END Tile_X1Y0_S4BEG[10]
  PIN Tile_X1Y0_S4BEG[11]
    DIRECTION OUTPUT ;
    USE SIGNAL ;
    ANTENNADIFFAREA 2.724000 ;
    PORT
      LAYER Metal2 ;
        RECT 387.160 0.000 387.560 0.400 ;
    END
  END Tile_X1Y0_S4BEG[11]
  PIN Tile_X1Y0_S4BEG[12]
    DIRECTION OUTPUT ;
    USE SIGNAL ;
    ANTENNADIFFAREA 2.724000 ;
    PORT
      LAYER Metal2 ;
        RECT 388.120 0.000 388.520 0.400 ;
    END
  END Tile_X1Y0_S4BEG[12]
  PIN Tile_X1Y0_S4BEG[13]
    DIRECTION OUTPUT ;
    USE SIGNAL ;
    ANTENNADIFFAREA 2.724000 ;
    PORT
      LAYER Metal2 ;
        RECT 389.080 0.000 389.480 0.400 ;
    END
  END Tile_X1Y0_S4BEG[13]
  PIN Tile_X1Y0_S4BEG[14]
    DIRECTION OUTPUT ;
    USE SIGNAL ;
    ANTENNADIFFAREA 2.724000 ;
    PORT
      LAYER Metal2 ;
        RECT 390.040 0.000 390.440 0.400 ;
    END
  END Tile_X1Y0_S4BEG[14]
  PIN Tile_X1Y0_S4BEG[15]
    DIRECTION OUTPUT ;
    USE SIGNAL ;
    ANTENNADIFFAREA 2.724000 ;
    PORT
      LAYER Metal2 ;
        RECT 391.000 0.000 391.400 0.400 ;
    END
  END Tile_X1Y0_S4BEG[15]
  PIN Tile_X1Y0_S4BEG[1]
    DIRECTION OUTPUT ;
    USE SIGNAL ;
    ANTENNADIFFAREA 2.724000 ;
    PORT
      LAYER Metal2 ;
        RECT 377.560 0.000 377.960 0.400 ;
    END
  END Tile_X1Y0_S4BEG[1]
  PIN Tile_X1Y0_S4BEG[2]
    DIRECTION OUTPUT ;
    USE SIGNAL ;
    ANTENNADIFFAREA 2.724000 ;
    PORT
      LAYER Metal2 ;
        RECT 378.520 0.000 378.920 0.400 ;
    END
  END Tile_X1Y0_S4BEG[2]
  PIN Tile_X1Y0_S4BEG[3]
    DIRECTION OUTPUT ;
    USE SIGNAL ;
    ANTENNADIFFAREA 2.724000 ;
    PORT
      LAYER Metal2 ;
        RECT 379.480 0.000 379.880 0.400 ;
    END
  END Tile_X1Y0_S4BEG[3]
  PIN Tile_X1Y0_S4BEG[4]
    DIRECTION OUTPUT ;
    USE SIGNAL ;
    ANTENNADIFFAREA 2.724000 ;
    PORT
      LAYER Metal2 ;
        RECT 380.440 0.000 380.840 0.400 ;
    END
  END Tile_X1Y0_S4BEG[4]
  PIN Tile_X1Y0_S4BEG[5]
    DIRECTION OUTPUT ;
    USE SIGNAL ;
    ANTENNADIFFAREA 2.724000 ;
    PORT
      LAYER Metal2 ;
        RECT 381.400 0.000 381.800 0.400 ;
    END
  END Tile_X1Y0_S4BEG[5]
  PIN Tile_X1Y0_S4BEG[6]
    DIRECTION OUTPUT ;
    USE SIGNAL ;
    ANTENNADIFFAREA 2.724000 ;
    PORT
      LAYER Metal2 ;
        RECT 382.360 0.000 382.760 0.400 ;
    END
  END Tile_X1Y0_S4BEG[6]
  PIN Tile_X1Y0_S4BEG[7]
    DIRECTION OUTPUT ;
    USE SIGNAL ;
    ANTENNADIFFAREA 2.724000 ;
    PORT
      LAYER Metal2 ;
        RECT 383.320 0.000 383.720 0.400 ;
    END
  END Tile_X1Y0_S4BEG[7]
  PIN Tile_X1Y0_S4BEG[8]
    DIRECTION OUTPUT ;
    USE SIGNAL ;
    ANTENNADIFFAREA 2.724000 ;
    PORT
      LAYER Metal2 ;
        RECT 384.280 0.000 384.680 0.400 ;
    END
  END Tile_X1Y0_S4BEG[8]
  PIN Tile_X1Y0_S4BEG[9]
    DIRECTION OUTPUT ;
    USE SIGNAL ;
    ANTENNADIFFAREA 2.724000 ;
    PORT
      LAYER Metal2 ;
        RECT 385.240 0.000 385.640 0.400 ;
    END
  END Tile_X1Y0_S4BEG[9]
  PIN Tile_X1Y0_SS4BEG[0]
    DIRECTION OUTPUT ;
    USE SIGNAL ;
    ANTENNADIFFAREA 2.724000 ;
    PORT
      LAYER Metal2 ;
        RECT 406.360 0.000 406.760 0.400 ;
    END
  END Tile_X1Y0_SS4BEG[0]
  PIN Tile_X1Y0_SS4BEG[10]
    DIRECTION OUTPUT ;
    USE SIGNAL ;
    ANTENNADIFFAREA 2.724000 ;
    PORT
      LAYER Metal2 ;
        RECT 415.960 0.000 416.360 0.400 ;
    END
  END Tile_X1Y0_SS4BEG[10]
  PIN Tile_X1Y0_SS4BEG[11]
    DIRECTION OUTPUT ;
    USE SIGNAL ;
    ANTENNADIFFAREA 2.724000 ;
    PORT
      LAYER Metal2 ;
        RECT 416.920 0.000 417.320 0.400 ;
    END
  END Tile_X1Y0_SS4BEG[11]
  PIN Tile_X1Y0_SS4BEG[12]
    DIRECTION OUTPUT ;
    USE SIGNAL ;
    ANTENNADIFFAREA 2.724000 ;
    PORT
      LAYER Metal2 ;
        RECT 417.880 0.000 418.280 0.400 ;
    END
  END Tile_X1Y0_SS4BEG[12]
  PIN Tile_X1Y0_SS4BEG[13]
    DIRECTION OUTPUT ;
    USE SIGNAL ;
    ANTENNADIFFAREA 2.724000 ;
    PORT
      LAYER Metal2 ;
        RECT 418.840 0.000 419.240 0.400 ;
    END
  END Tile_X1Y0_SS4BEG[13]
  PIN Tile_X1Y0_SS4BEG[14]
    DIRECTION OUTPUT ;
    USE SIGNAL ;
    ANTENNADIFFAREA 2.724000 ;
    PORT
      LAYER Metal2 ;
        RECT 419.800 0.000 420.200 0.400 ;
    END
  END Tile_X1Y0_SS4BEG[14]
  PIN Tile_X1Y0_SS4BEG[15]
    DIRECTION OUTPUT ;
    USE SIGNAL ;
    ANTENNADIFFAREA 2.724000 ;
    PORT
      LAYER Metal2 ;
        RECT 420.760 0.000 421.160 0.400 ;
    END
  END Tile_X1Y0_SS4BEG[15]
  PIN Tile_X1Y0_SS4BEG[1]
    DIRECTION OUTPUT ;
    USE SIGNAL ;
    ANTENNADIFFAREA 2.724000 ;
    PORT
      LAYER Metal2 ;
        RECT 407.320 0.000 407.720 0.400 ;
    END
  END Tile_X1Y0_SS4BEG[1]
  PIN Tile_X1Y0_SS4BEG[2]
    DIRECTION OUTPUT ;
    USE SIGNAL ;
    ANTENNADIFFAREA 2.724000 ;
    PORT
      LAYER Metal2 ;
        RECT 408.280 0.000 408.680 0.400 ;
    END
  END Tile_X1Y0_SS4BEG[2]
  PIN Tile_X1Y0_SS4BEG[3]
    DIRECTION OUTPUT ;
    USE SIGNAL ;
    ANTENNADIFFAREA 2.724000 ;
    PORT
      LAYER Metal2 ;
        RECT 409.240 0.000 409.640 0.400 ;
    END
  END Tile_X1Y0_SS4BEG[3]
  PIN Tile_X1Y0_SS4BEG[4]
    DIRECTION OUTPUT ;
    USE SIGNAL ;
    ANTENNADIFFAREA 2.724000 ;
    PORT
      LAYER Metal2 ;
        RECT 410.200 0.000 410.600 0.400 ;
    END
  END Tile_X1Y0_SS4BEG[4]
  PIN Tile_X1Y0_SS4BEG[5]
    DIRECTION OUTPUT ;
    USE SIGNAL ;
    ANTENNADIFFAREA 2.724000 ;
    PORT
      LAYER Metal2 ;
        RECT 411.160 0.000 411.560 0.400 ;
    END
  END Tile_X1Y0_SS4BEG[5]
  PIN Tile_X1Y0_SS4BEG[6]
    DIRECTION OUTPUT ;
    USE SIGNAL ;
    ANTENNADIFFAREA 2.724000 ;
    PORT
      LAYER Metal2 ;
        RECT 412.120 0.000 412.520 0.400 ;
    END
  END Tile_X1Y0_SS4BEG[6]
  PIN Tile_X1Y0_SS4BEG[7]
    DIRECTION OUTPUT ;
    USE SIGNAL ;
    ANTENNADIFFAREA 2.724000 ;
    PORT
      LAYER Metal2 ;
        RECT 413.080 0.000 413.480 0.400 ;
    END
  END Tile_X1Y0_SS4BEG[7]
  PIN Tile_X1Y0_SS4BEG[8]
    DIRECTION OUTPUT ;
    USE SIGNAL ;
    ANTENNADIFFAREA 2.724000 ;
    PORT
      LAYER Metal2 ;
        RECT 414.040 0.000 414.440 0.400 ;
    END
  END Tile_X1Y0_SS4BEG[8]
  PIN Tile_X1Y0_SS4BEG[9]
    DIRECTION OUTPUT ;
    USE SIGNAL ;
    ANTENNADIFFAREA 2.724000 ;
    PORT
      LAYER Metal2 ;
        RECT 415.000 0.000 415.400 0.400 ;
    END
  END Tile_X1Y0_SS4BEG[9]
  PIN Tile_X1Y0_UserCLKo
    DIRECTION OUTPUT ;
    USE SIGNAL ;
    ANTENNADIFFAREA 2.724000 ;
    PORT
      LAYER Metal3 ;
        RECT 466.160 1.900 466.560 2.300 ;
    END
  END Tile_X1Y0_UserCLKo
  PIN VGND
    DIRECTION INOUT ;
    USE GROUND ;
    PORT
      LAYER Metal4 ;
        RECT 15.380 0.000 16.380 79.380 ;
    END
    PORT
      LAYER Metal4 ;
        RECT 65.380 0.000 66.380 79.380 ;
    END
    PORT
      LAYER Metal4 ;
        RECT 115.380 0.000 116.380 79.380 ;
    END
    PORT
      LAYER Metal4 ;
        RECT 165.380 0.000 166.380 79.380 ;
    END
    PORT
      LAYER Metal4 ;
        RECT 215.380 0.000 216.380 79.380 ;
    END
    PORT
      LAYER Metal4 ;
        RECT 248.660 0.000 249.660 79.380 ;
    END
    PORT
      LAYER Metal4 ;
        RECT 298.660 0.000 299.660 79.380 ;
    END
    PORT
      LAYER Metal4 ;
        RECT 348.660 0.000 349.660 79.380 ;
    END
    PORT
      LAYER Metal4 ;
        RECT 398.660 0.000 399.660 79.380 ;
    END
    PORT
      LAYER Metal4 ;
        RECT 448.660 0.000 449.660 79.380 ;
    END
  END VGND
  PIN VPWR
    DIRECTION INOUT ;
    USE POWER ;
    PORT
      LAYER Metal4 ;
        RECT 12.380 0.000 13.380 79.380 ;
    END
    PORT
      LAYER Metal4 ;
        RECT 62.380 0.000 63.380 79.380 ;
    END
    PORT
      LAYER Metal4 ;
        RECT 112.380 0.000 113.380 79.380 ;
    END
    PORT
      LAYER Metal4 ;
        RECT 162.380 0.000 163.380 79.380 ;
    END
    PORT
      LAYER Metal4 ;
        RECT 212.380 0.000 213.380 79.380 ;
    END
    PORT
      LAYER Metal4 ;
        RECT 245.660 0.000 246.660 79.380 ;
    END
    PORT
      LAYER Metal4 ;
        RECT 295.660 0.000 296.660 79.380 ;
    END
    PORT
      LAYER Metal4 ;
        RECT 345.660 0.000 346.660 79.380 ;
    END
    PORT
      LAYER Metal4 ;
        RECT 395.660 0.000 396.660 79.380 ;
    END
    PORT
      LAYER Metal4 ;
        RECT 445.660 0.000 446.660 79.380 ;
    END
  END VPWR
  OBS
      LAYER GatPoly ;
        RECT 2.880 3.630 463.680 75.750 ;
      LAYER Metal1 ;
        RECT 2.880 3.560 463.680 75.820 ;
      LAYER Metal2 ;
        RECT 0.375 78.770 6.790 79.060 ;
        RECT 7.610 78.770 18.310 79.060 ;
        RECT 19.130 78.770 29.830 79.060 ;
        RECT 30.650 78.770 41.350 79.060 ;
        RECT 42.170 78.770 52.870 79.060 ;
        RECT 53.690 78.770 64.390 79.060 ;
        RECT 65.210 78.770 75.910 79.060 ;
        RECT 76.730 78.770 87.430 79.060 ;
        RECT 88.250 78.770 98.950 79.060 ;
        RECT 99.770 78.770 110.470 79.060 ;
        RECT 111.290 78.770 121.990 79.060 ;
        RECT 122.810 78.770 133.510 79.060 ;
        RECT 134.330 78.770 145.030 79.060 ;
        RECT 145.850 78.770 156.550 79.060 ;
        RECT 157.370 78.770 168.070 79.060 ;
        RECT 168.890 78.770 179.590 79.060 ;
        RECT 180.410 78.770 191.110 79.060 ;
        RECT 191.930 78.770 202.630 79.060 ;
        RECT 203.450 78.770 214.150 79.060 ;
        RECT 214.970 78.770 225.670 79.060 ;
        RECT 226.490 78.770 241.030 79.060 ;
        RECT 241.850 78.770 245.830 79.060 ;
        RECT 246.650 78.770 250.630 79.060 ;
        RECT 251.450 78.770 255.430 79.060 ;
        RECT 256.250 78.770 260.230 79.060 ;
        RECT 261.050 78.770 265.030 79.060 ;
        RECT 265.850 78.770 269.830 79.060 ;
        RECT 270.650 78.770 274.630 79.060 ;
        RECT 275.450 78.770 279.430 79.060 ;
        RECT 280.250 78.770 284.230 79.060 ;
        RECT 285.050 78.770 289.030 79.060 ;
        RECT 289.850 78.770 293.830 79.060 ;
        RECT 294.650 78.770 298.630 79.060 ;
        RECT 299.450 78.770 303.430 79.060 ;
        RECT 304.250 78.770 308.230 79.060 ;
        RECT 309.050 78.770 313.030 79.060 ;
        RECT 313.850 78.770 317.830 79.060 ;
        RECT 318.650 78.770 322.630 79.060 ;
        RECT 323.450 78.770 327.430 79.060 ;
        RECT 328.250 78.770 332.230 79.060 ;
        RECT 333.050 78.770 347.590 79.060 ;
        RECT 348.410 78.770 352.390 79.060 ;
        RECT 353.210 78.770 357.190 79.060 ;
        RECT 358.010 78.770 361.990 79.060 ;
        RECT 362.810 78.770 366.790 79.060 ;
        RECT 367.610 78.770 371.590 79.060 ;
        RECT 372.410 78.770 376.390 79.060 ;
        RECT 377.210 78.770 381.190 79.060 ;
        RECT 382.010 78.770 385.990 79.060 ;
        RECT 386.810 78.770 390.790 79.060 ;
        RECT 391.610 78.770 395.590 79.060 ;
        RECT 396.410 78.770 400.390 79.060 ;
        RECT 401.210 78.770 405.190 79.060 ;
        RECT 406.010 78.770 409.990 79.060 ;
        RECT 410.810 78.770 414.790 79.060 ;
        RECT 415.610 78.770 419.590 79.060 ;
        RECT 420.410 78.770 424.390 79.060 ;
        RECT 425.210 78.770 429.190 79.060 ;
        RECT 430.010 78.770 433.990 79.060 ;
        RECT 434.810 78.770 438.790 79.060 ;
        RECT 439.610 78.770 443.590 79.060 ;
        RECT 444.410 78.770 448.390 79.060 ;
        RECT 449.210 78.770 453.190 79.060 ;
        RECT 454.010 78.770 457.990 79.060 ;
        RECT 458.810 78.770 462.825 79.060 ;
        RECT 0.375 0.610 462.825 78.770 ;
        RECT 0.375 0.275 1.030 0.610 ;
        RECT 1.850 0.275 2.950 0.610 ;
        RECT 3.770 0.275 4.870 0.610 ;
        RECT 5.690 0.275 6.790 0.610 ;
        RECT 7.610 0.275 11.590 0.610 ;
        RECT 12.410 0.275 12.550 0.610 ;
        RECT 13.370 0.275 13.510 0.610 ;
        RECT 14.330 0.275 14.470 0.610 ;
        RECT 15.290 0.275 15.430 0.610 ;
        RECT 16.250 0.275 16.390 0.610 ;
        RECT 17.210 0.275 17.350 0.610 ;
        RECT 18.170 0.275 18.310 0.610 ;
        RECT 19.130 0.275 25.990 0.610 ;
        RECT 26.810 0.275 26.950 0.610 ;
        RECT 27.770 0.275 27.910 0.610 ;
        RECT 28.730 0.275 28.870 0.610 ;
        RECT 29.690 0.275 29.830 0.610 ;
        RECT 30.650 0.275 30.790 0.610 ;
        RECT 31.610 0.275 31.750 0.610 ;
        RECT 32.570 0.275 32.710 0.610 ;
        RECT 33.530 0.275 44.230 0.610 ;
        RECT 45.050 0.275 45.190 0.610 ;
        RECT 46.010 0.275 46.150 0.610 ;
        RECT 46.970 0.275 47.110 0.610 ;
        RECT 47.930 0.275 48.070 0.610 ;
        RECT 48.890 0.275 49.030 0.610 ;
        RECT 49.850 0.275 49.990 0.610 ;
        RECT 50.810 0.275 50.950 0.610 ;
        RECT 51.770 0.275 51.910 0.610 ;
        RECT 52.730 0.275 52.870 0.610 ;
        RECT 53.690 0.275 53.830 0.610 ;
        RECT 54.650 0.275 54.790 0.610 ;
        RECT 55.610 0.275 55.750 0.610 ;
        RECT 56.570 0.275 56.710 0.610 ;
        RECT 57.530 0.275 57.670 0.610 ;
        RECT 58.490 0.275 58.630 0.610 ;
        RECT 59.450 0.275 73.990 0.610 ;
        RECT 74.810 0.275 74.950 0.610 ;
        RECT 75.770 0.275 75.910 0.610 ;
        RECT 76.730 0.275 76.870 0.610 ;
        RECT 77.690 0.275 77.830 0.610 ;
        RECT 78.650 0.275 78.790 0.610 ;
        RECT 79.610 0.275 79.750 0.610 ;
        RECT 80.570 0.275 80.710 0.610 ;
        RECT 81.530 0.275 81.670 0.610 ;
        RECT 82.490 0.275 82.630 0.610 ;
        RECT 83.450 0.275 83.590 0.610 ;
        RECT 84.410 0.275 84.550 0.610 ;
        RECT 85.370 0.275 85.510 0.610 ;
        RECT 86.330 0.275 86.470 0.610 ;
        RECT 87.290 0.275 87.430 0.610 ;
        RECT 88.250 0.275 88.390 0.610 ;
        RECT 89.210 0.275 97.030 0.610 ;
        RECT 97.850 0.275 98.950 0.610 ;
        RECT 99.770 0.275 100.870 0.610 ;
        RECT 101.690 0.275 102.790 0.610 ;
        RECT 103.610 0.275 104.710 0.610 ;
        RECT 105.530 0.275 106.630 0.610 ;
        RECT 107.450 0.275 108.550 0.610 ;
        RECT 109.370 0.275 110.470 0.610 ;
        RECT 111.290 0.275 112.390 0.610 ;
        RECT 113.210 0.275 114.310 0.610 ;
        RECT 115.130 0.275 116.230 0.610 ;
        RECT 117.050 0.275 118.150 0.610 ;
        RECT 118.970 0.275 120.070 0.610 ;
        RECT 120.890 0.275 124.870 0.610 ;
        RECT 125.690 0.275 125.830 0.610 ;
        RECT 126.650 0.275 126.790 0.610 ;
        RECT 127.610 0.275 127.750 0.610 ;
        RECT 128.570 0.275 128.710 0.610 ;
        RECT 129.530 0.275 129.670 0.610 ;
        RECT 130.490 0.275 130.630 0.610 ;
        RECT 131.450 0.275 131.590 0.610 ;
        RECT 132.410 0.275 143.110 0.610 ;
        RECT 143.930 0.275 144.070 0.610 ;
        RECT 144.890 0.275 145.030 0.610 ;
        RECT 145.850 0.275 145.990 0.610 ;
        RECT 146.810 0.275 146.950 0.610 ;
        RECT 147.770 0.275 147.910 0.610 ;
        RECT 148.730 0.275 148.870 0.610 ;
        RECT 149.690 0.275 149.830 0.610 ;
        RECT 150.650 0.275 150.790 0.610 ;
        RECT 151.610 0.275 151.750 0.610 ;
        RECT 152.570 0.275 152.710 0.610 ;
        RECT 153.530 0.275 153.670 0.610 ;
        RECT 154.490 0.275 154.630 0.610 ;
        RECT 155.450 0.275 155.590 0.610 ;
        RECT 156.410 0.275 156.550 0.610 ;
        RECT 157.370 0.275 157.510 0.610 ;
        RECT 158.330 0.275 172.870 0.610 ;
        RECT 173.690 0.275 173.830 0.610 ;
        RECT 174.650 0.275 174.790 0.610 ;
        RECT 175.610 0.275 175.750 0.610 ;
        RECT 176.570 0.275 176.710 0.610 ;
        RECT 177.530 0.275 177.670 0.610 ;
        RECT 178.490 0.275 178.630 0.610 ;
        RECT 179.450 0.275 179.590 0.610 ;
        RECT 180.410 0.275 180.550 0.610 ;
        RECT 181.370 0.275 181.510 0.610 ;
        RECT 182.330 0.275 182.470 0.610 ;
        RECT 183.290 0.275 183.430 0.610 ;
        RECT 184.250 0.275 184.390 0.610 ;
        RECT 185.210 0.275 185.350 0.610 ;
        RECT 186.170 0.275 186.310 0.610 ;
        RECT 187.130 0.275 187.270 0.610 ;
        RECT 188.090 0.275 204.550 0.610 ;
        RECT 205.370 0.275 205.510 0.610 ;
        RECT 206.330 0.275 206.470 0.610 ;
        RECT 207.290 0.275 207.430 0.610 ;
        RECT 208.250 0.275 208.390 0.610 ;
        RECT 209.210 0.275 209.350 0.610 ;
        RECT 210.170 0.275 210.310 0.610 ;
        RECT 211.130 0.275 211.270 0.610 ;
        RECT 212.090 0.275 212.230 0.610 ;
        RECT 213.050 0.275 213.190 0.610 ;
        RECT 214.010 0.275 214.150 0.610 ;
        RECT 214.970 0.275 215.110 0.610 ;
        RECT 215.930 0.275 216.070 0.610 ;
        RECT 216.890 0.275 217.030 0.610 ;
        RECT 217.850 0.275 217.990 0.610 ;
        RECT 218.810 0.275 218.950 0.610 ;
        RECT 219.770 0.275 219.910 0.610 ;
        RECT 220.730 0.275 220.870 0.610 ;
        RECT 221.690 0.275 221.830 0.610 ;
        RECT 222.650 0.275 222.790 0.610 ;
        RECT 223.610 0.275 234.310 0.610 ;
        RECT 235.130 0.275 236.230 0.610 ;
        RECT 237.050 0.275 238.150 0.610 ;
        RECT 238.970 0.275 240.070 0.610 ;
        RECT 240.890 0.275 244.870 0.610 ;
        RECT 245.690 0.275 245.830 0.610 ;
        RECT 246.650 0.275 246.790 0.610 ;
        RECT 247.610 0.275 247.750 0.610 ;
        RECT 248.570 0.275 248.710 0.610 ;
        RECT 249.530 0.275 249.670 0.610 ;
        RECT 250.490 0.275 250.630 0.610 ;
        RECT 251.450 0.275 251.590 0.610 ;
        RECT 252.410 0.275 259.270 0.610 ;
        RECT 260.090 0.275 260.230 0.610 ;
        RECT 261.050 0.275 261.190 0.610 ;
        RECT 262.010 0.275 262.150 0.610 ;
        RECT 262.970 0.275 263.110 0.610 ;
        RECT 263.930 0.275 264.070 0.610 ;
        RECT 264.890 0.275 265.030 0.610 ;
        RECT 265.850 0.275 265.990 0.610 ;
        RECT 266.810 0.275 277.510 0.610 ;
        RECT 278.330 0.275 278.470 0.610 ;
        RECT 279.290 0.275 279.430 0.610 ;
        RECT 280.250 0.275 280.390 0.610 ;
        RECT 281.210 0.275 281.350 0.610 ;
        RECT 282.170 0.275 282.310 0.610 ;
        RECT 283.130 0.275 283.270 0.610 ;
        RECT 284.090 0.275 284.230 0.610 ;
        RECT 285.050 0.275 285.190 0.610 ;
        RECT 286.010 0.275 286.150 0.610 ;
        RECT 286.970 0.275 287.110 0.610 ;
        RECT 287.930 0.275 288.070 0.610 ;
        RECT 288.890 0.275 289.030 0.610 ;
        RECT 289.850 0.275 289.990 0.610 ;
        RECT 290.810 0.275 290.950 0.610 ;
        RECT 291.770 0.275 291.910 0.610 ;
        RECT 292.730 0.275 307.270 0.610 ;
        RECT 308.090 0.275 308.230 0.610 ;
        RECT 309.050 0.275 309.190 0.610 ;
        RECT 310.010 0.275 310.150 0.610 ;
        RECT 310.970 0.275 311.110 0.610 ;
        RECT 311.930 0.275 312.070 0.610 ;
        RECT 312.890 0.275 313.030 0.610 ;
        RECT 313.850 0.275 313.990 0.610 ;
        RECT 314.810 0.275 314.950 0.610 ;
        RECT 315.770 0.275 315.910 0.610 ;
        RECT 316.730 0.275 316.870 0.610 ;
        RECT 317.690 0.275 317.830 0.610 ;
        RECT 318.650 0.275 318.790 0.610 ;
        RECT 319.610 0.275 319.750 0.610 ;
        RECT 320.570 0.275 320.710 0.610 ;
        RECT 321.530 0.275 321.670 0.610 ;
        RECT 322.490 0.275 330.310 0.610 ;
        RECT 331.130 0.275 332.230 0.610 ;
        RECT 333.050 0.275 334.150 0.610 ;
        RECT 334.970 0.275 336.070 0.610 ;
        RECT 336.890 0.275 337.990 0.610 ;
        RECT 338.810 0.275 339.910 0.610 ;
        RECT 340.730 0.275 341.830 0.610 ;
        RECT 342.650 0.275 343.750 0.610 ;
        RECT 344.570 0.275 345.670 0.610 ;
        RECT 346.490 0.275 347.590 0.610 ;
        RECT 348.410 0.275 349.510 0.610 ;
        RECT 350.330 0.275 351.430 0.610 ;
        RECT 352.250 0.275 353.350 0.610 ;
        RECT 354.170 0.275 358.150 0.610 ;
        RECT 358.970 0.275 359.110 0.610 ;
        RECT 359.930 0.275 360.070 0.610 ;
        RECT 360.890 0.275 361.030 0.610 ;
        RECT 361.850 0.275 361.990 0.610 ;
        RECT 362.810 0.275 362.950 0.610 ;
        RECT 363.770 0.275 363.910 0.610 ;
        RECT 364.730 0.275 364.870 0.610 ;
        RECT 365.690 0.275 376.390 0.610 ;
        RECT 377.210 0.275 377.350 0.610 ;
        RECT 378.170 0.275 378.310 0.610 ;
        RECT 379.130 0.275 379.270 0.610 ;
        RECT 380.090 0.275 380.230 0.610 ;
        RECT 381.050 0.275 381.190 0.610 ;
        RECT 382.010 0.275 382.150 0.610 ;
        RECT 382.970 0.275 383.110 0.610 ;
        RECT 383.930 0.275 384.070 0.610 ;
        RECT 384.890 0.275 385.030 0.610 ;
        RECT 385.850 0.275 385.990 0.610 ;
        RECT 386.810 0.275 386.950 0.610 ;
        RECT 387.770 0.275 387.910 0.610 ;
        RECT 388.730 0.275 388.870 0.610 ;
        RECT 389.690 0.275 389.830 0.610 ;
        RECT 390.650 0.275 390.790 0.610 ;
        RECT 391.610 0.275 406.150 0.610 ;
        RECT 406.970 0.275 407.110 0.610 ;
        RECT 407.930 0.275 408.070 0.610 ;
        RECT 408.890 0.275 409.030 0.610 ;
        RECT 409.850 0.275 409.990 0.610 ;
        RECT 410.810 0.275 410.950 0.610 ;
        RECT 411.770 0.275 411.910 0.610 ;
        RECT 412.730 0.275 412.870 0.610 ;
        RECT 413.690 0.275 413.830 0.610 ;
        RECT 414.650 0.275 414.790 0.610 ;
        RECT 415.610 0.275 415.750 0.610 ;
        RECT 416.570 0.275 416.710 0.610 ;
        RECT 417.530 0.275 417.670 0.610 ;
        RECT 418.490 0.275 418.630 0.610 ;
        RECT 419.450 0.275 419.590 0.610 ;
        RECT 420.410 0.275 420.550 0.610 ;
        RECT 421.370 0.275 437.830 0.610 ;
        RECT 438.650 0.275 438.790 0.610 ;
        RECT 439.610 0.275 439.750 0.610 ;
        RECT 440.570 0.275 440.710 0.610 ;
        RECT 441.530 0.275 441.670 0.610 ;
        RECT 442.490 0.275 442.630 0.610 ;
        RECT 443.450 0.275 443.590 0.610 ;
        RECT 444.410 0.275 444.550 0.610 ;
        RECT 445.370 0.275 445.510 0.610 ;
        RECT 446.330 0.275 446.470 0.610 ;
        RECT 447.290 0.275 447.430 0.610 ;
        RECT 448.250 0.275 448.390 0.610 ;
        RECT 449.210 0.275 449.350 0.610 ;
        RECT 450.170 0.275 450.310 0.610 ;
        RECT 451.130 0.275 451.270 0.610 ;
        RECT 452.090 0.275 452.230 0.610 ;
        RECT 453.050 0.275 453.190 0.610 ;
        RECT 454.010 0.275 454.150 0.610 ;
        RECT 454.970 0.275 455.110 0.610 ;
        RECT 455.930 0.275 456.070 0.610 ;
        RECT 456.890 0.275 462.825 0.610 ;
      LAYER Metal3 ;
        RECT 0.335 68.030 466.180 79.065 ;
        RECT 0.610 67.210 465.950 68.030 ;
        RECT 0.335 66.350 466.180 67.210 ;
        RECT 0.610 65.530 465.950 66.350 ;
        RECT 0.335 64.670 466.180 65.530 ;
        RECT 0.610 63.850 465.950 64.670 ;
        RECT 0.335 62.990 466.180 63.850 ;
        RECT 0.610 62.170 465.950 62.990 ;
        RECT 0.335 61.310 466.180 62.170 ;
        RECT 0.610 60.490 465.950 61.310 ;
        RECT 0.335 59.630 466.180 60.490 ;
        RECT 0.610 58.810 465.950 59.630 ;
        RECT 0.335 57.950 466.180 58.810 ;
        RECT 0.610 57.130 465.950 57.950 ;
        RECT 0.335 56.270 466.180 57.130 ;
        RECT 0.610 55.450 465.950 56.270 ;
        RECT 0.335 54.590 466.180 55.450 ;
        RECT 0.610 53.770 465.950 54.590 ;
        RECT 0.335 52.910 466.180 53.770 ;
        RECT 0.610 52.090 465.950 52.910 ;
        RECT 0.335 51.230 466.180 52.090 ;
        RECT 0.610 50.410 465.950 51.230 ;
        RECT 0.335 49.550 466.180 50.410 ;
        RECT 0.610 48.730 465.950 49.550 ;
        RECT 0.335 47.870 466.180 48.730 ;
        RECT 0.610 47.050 465.950 47.870 ;
        RECT 0.335 46.190 466.180 47.050 ;
        RECT 0.610 45.370 465.950 46.190 ;
        RECT 0.335 44.510 466.180 45.370 ;
        RECT 0.610 43.690 465.950 44.510 ;
        RECT 0.335 42.830 466.180 43.690 ;
        RECT 0.610 42.010 465.950 42.830 ;
        RECT 0.335 41.150 466.180 42.010 ;
        RECT 0.610 40.330 465.950 41.150 ;
        RECT 0.335 39.470 466.180 40.330 ;
        RECT 0.610 38.650 465.950 39.470 ;
        RECT 0.335 37.790 466.180 38.650 ;
        RECT 0.610 36.970 465.950 37.790 ;
        RECT 0.335 36.110 466.180 36.970 ;
        RECT 0.610 35.290 465.950 36.110 ;
        RECT 0.335 34.430 466.180 35.290 ;
        RECT 0.610 33.610 465.950 34.430 ;
        RECT 0.335 32.750 466.180 33.610 ;
        RECT 0.610 31.930 465.950 32.750 ;
        RECT 0.335 31.070 466.180 31.930 ;
        RECT 0.610 30.250 465.950 31.070 ;
        RECT 0.335 29.390 466.180 30.250 ;
        RECT 0.610 28.570 465.950 29.390 ;
        RECT 0.335 27.710 466.180 28.570 ;
        RECT 0.610 26.890 465.950 27.710 ;
        RECT 0.335 26.030 466.180 26.890 ;
        RECT 0.610 25.210 465.950 26.030 ;
        RECT 0.335 24.350 466.180 25.210 ;
        RECT 0.610 23.530 465.950 24.350 ;
        RECT 0.335 22.670 466.180 23.530 ;
        RECT 0.610 21.850 465.950 22.670 ;
        RECT 0.335 20.990 466.180 21.850 ;
        RECT 0.610 20.170 465.950 20.990 ;
        RECT 0.335 19.310 466.180 20.170 ;
        RECT 0.610 18.490 465.950 19.310 ;
        RECT 0.335 17.630 466.180 18.490 ;
        RECT 0.610 16.810 465.950 17.630 ;
        RECT 0.335 15.950 466.180 16.810 ;
        RECT 0.610 15.130 465.950 15.950 ;
        RECT 0.335 2.510 466.180 15.130 ;
        RECT 0.610 1.690 465.950 2.510 ;
        RECT 0.335 0.315 466.180 1.690 ;
      LAYER Metal4 ;
        RECT 29.660 0.275 62.170 79.105 ;
        RECT 63.590 0.275 65.170 79.105 ;
        RECT 66.590 0.275 112.170 79.105 ;
        RECT 113.590 0.275 115.170 79.105 ;
        RECT 116.590 0.275 162.170 79.105 ;
        RECT 163.590 0.275 165.170 79.105 ;
        RECT 166.590 0.275 212.170 79.105 ;
        RECT 213.590 0.275 215.170 79.105 ;
        RECT 216.590 0.275 245.450 79.105 ;
        RECT 246.870 0.275 248.450 79.105 ;
        RECT 249.870 0.275 295.450 79.105 ;
        RECT 296.870 0.275 298.450 79.105 ;
        RECT 299.870 0.275 345.450 79.105 ;
        RECT 346.870 0.275 348.450 79.105 ;
        RECT 349.870 0.275 395.450 79.105 ;
        RECT 396.870 0.275 398.450 79.105 ;
        RECT 399.870 0.275 445.450 79.105 ;
        RECT 446.870 0.275 447.670 79.105 ;
      LAYER TopMetal1 ;
        RECT 98.540 5.380 448.180 77.700 ;
  END
END EXT_PMOD
END LIBRARY

